VERSION 5.7 ;
BUSBITCHARS "[]" ;
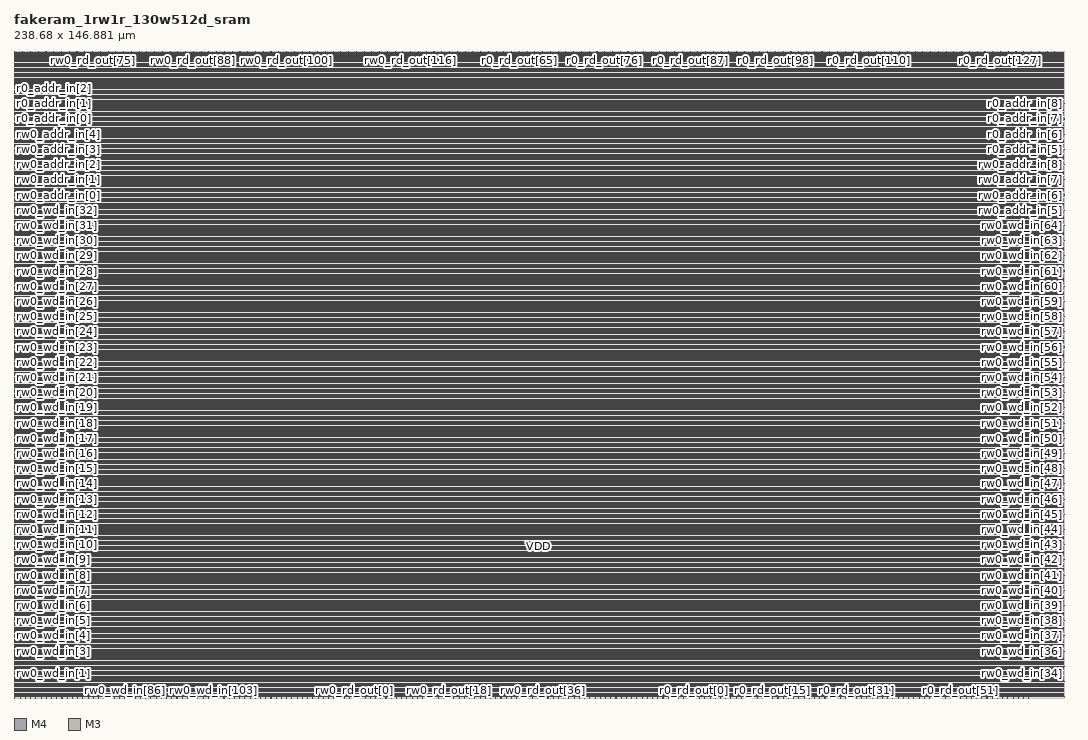
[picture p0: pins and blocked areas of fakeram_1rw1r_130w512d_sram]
MACRO fakeram_1rw1r_130w512d_sram
  FOREIGN fakeram_1rw1r_130w512d_sram 0 0 ;
  SYMMETRY X Y R90 ;
  SIZE 238.680 BY 146.881 ;
  CLASS BLOCK ;
  PIN rw0_wd_in[0]
    DIRECTION INPUT ;
    USE SIGNAL ;
    SHAPE ABUTMENT ;
    PORT
      LAYER M4 ;
      RECT 0.000 0.276 0.072 0.300 ;
    END
  END rw0_wd_in[0]
  PIN rw0_wd_in[1]
    DIRECTION INPUT ;
    USE SIGNAL ;
    SHAPE ABUTMENT ;
    PORT
      LAYER M4 ;
      RECT 0.000 3.732 0.072 3.756 ;
    END
  END rw0_wd_in[1]
  PIN rw0_wd_in[2]
    DIRECTION INPUT ;
    USE SIGNAL ;
    SHAPE ABUTMENT ;
    PORT
      LAYER M4 ;
      RECT 0.000 7.188 0.072 7.212 ;
    END
  END rw0_wd_in[2]
  PIN rw0_wd_in[3]
    DIRECTION INPUT ;
    USE SIGNAL ;
    SHAPE ABUTMENT ;
    PORT
      LAYER M4 ;
      RECT 0.000 10.644 0.072 10.668 ;
    END
  END rw0_wd_in[3]
  PIN rw0_wd_in[4]
    DIRECTION INPUT ;
    USE SIGNAL ;
    SHAPE ABUTMENT ;
    PORT
      LAYER M4 ;
      RECT 0.000 14.100 0.072 14.124 ;
    END
  END rw0_wd_in[4]
  PIN rw0_wd_in[5]
    DIRECTION INPUT ;
    USE SIGNAL ;
    SHAPE ABUTMENT ;
    PORT
      LAYER M4 ;
      RECT 0.000 17.556 0.072 17.580 ;
    END
  END rw0_wd_in[5]
  PIN rw0_wd_in[6]
    DIRECTION INPUT ;
    USE SIGNAL ;
    SHAPE ABUTMENT ;
    PORT
      LAYER M4 ;
      RECT 0.000 21.012 0.072 21.036 ;
    END
  END rw0_wd_in[6]
  PIN rw0_wd_in[7]
    DIRECTION INPUT ;
    USE SIGNAL ;
    SHAPE ABUTMENT ;
    PORT
      LAYER M4 ;
      RECT 0.000 24.468 0.072 24.492 ;
    END
  END rw0_wd_in[7]
  PIN rw0_wd_in[8]
    DIRECTION INPUT ;
    USE SIGNAL ;
    SHAPE ABUTMENT ;
    PORT
      LAYER M4 ;
      RECT 0.000 27.924 0.072 27.948 ;
    END
  END rw0_wd_in[8]
  PIN rw0_wd_in[9]
    DIRECTION INPUT ;
    USE SIGNAL ;
    SHAPE ABUTMENT ;
    PORT
      LAYER M4 ;
      RECT 0.000 31.380 0.072 31.404 ;
    END
  END rw0_wd_in[9]
  PIN rw0_wd_in[10]
    DIRECTION INPUT ;
    USE SIGNAL ;
    SHAPE ABUTMENT ;
    PORT
      LAYER M4 ;
      RECT 0.000 34.836 0.072 34.860 ;
    END
  END rw0_wd_in[10]
  PIN rw0_wd_in[11]
    DIRECTION INPUT ;
    USE SIGNAL ;
    SHAPE ABUTMENT ;
    PORT
      LAYER M4 ;
      RECT 0.000 38.292 0.072 38.316 ;
    END
  END rw0_wd_in[11]
  PIN rw0_wd_in[12]
    DIRECTION INPUT ;
    USE SIGNAL ;
    SHAPE ABUTMENT ;
    PORT
      LAYER M4 ;
      RECT 0.000 41.748 0.072 41.772 ;
    END
  END rw0_wd_in[12]
  PIN rw0_wd_in[13]
    DIRECTION INPUT ;
    USE SIGNAL ;
    SHAPE ABUTMENT ;
    PORT
      LAYER M4 ;
      RECT 0.000 45.204 0.072 45.228 ;
    END
  END rw0_wd_in[13]
  PIN rw0_wd_in[14]
    DIRECTION INPUT ;
    USE SIGNAL ;
    SHAPE ABUTMENT ;
    PORT
      LAYER M4 ;
      RECT 0.000 48.660 0.072 48.684 ;
    END
  END rw0_wd_in[14]
  PIN rw0_wd_in[15]
    DIRECTION INPUT ;
    USE SIGNAL ;
    SHAPE ABUTMENT ;
    PORT
      LAYER M4 ;
      RECT 0.000 52.116 0.072 52.140 ;
    END
  END rw0_wd_in[15]
  PIN rw0_wd_in[16]
    DIRECTION INPUT ;
    USE SIGNAL ;
    SHAPE ABUTMENT ;
    PORT
      LAYER M4 ;
      RECT 0.000 55.572 0.072 55.596 ;
    END
  END rw0_wd_in[16]
  PIN rw0_wd_in[17]
    DIRECTION INPUT ;
    USE SIGNAL ;
    SHAPE ABUTMENT ;
    PORT
      LAYER M4 ;
      RECT 0.000 59.028 0.072 59.052 ;
    END
  END rw0_wd_in[17]
  PIN rw0_wd_in[18]
    DIRECTION INPUT ;
    USE SIGNAL ;
    SHAPE ABUTMENT ;
    PORT
      LAYER M4 ;
      RECT 0.000 62.484 0.072 62.508 ;
    END
  END rw0_wd_in[18]
  PIN rw0_wd_in[19]
    DIRECTION INPUT ;
    USE SIGNAL ;
    SHAPE ABUTMENT ;
    PORT
      LAYER M4 ;
      RECT 0.000 65.940 0.072 65.964 ;
    END
  END rw0_wd_in[19]
  PIN rw0_wd_in[20]
    DIRECTION INPUT ;
    USE SIGNAL ;
    SHAPE ABUTMENT ;
    PORT
      LAYER M4 ;
      RECT 0.000 69.396 0.072 69.420 ;
    END
  END rw0_wd_in[20]
  PIN rw0_wd_in[21]
    DIRECTION INPUT ;
    USE SIGNAL ;
    SHAPE ABUTMENT ;
    PORT
      LAYER M4 ;
      RECT 0.000 72.852 0.072 72.876 ;
    END
  END rw0_wd_in[21]
  PIN rw0_wd_in[22]
    DIRECTION INPUT ;
    USE SIGNAL ;
    SHAPE ABUTMENT ;
    PORT
      LAYER M4 ;
      RECT 0.000 76.308 0.072 76.332 ;
    END
  END rw0_wd_in[22]
  PIN rw0_wd_in[23]
    DIRECTION INPUT ;
    USE SIGNAL ;
    SHAPE ABUTMENT ;
    PORT
      LAYER M4 ;
      RECT 0.000 79.764 0.072 79.788 ;
    END
  END rw0_wd_in[23]
  PIN rw0_wd_in[24]
    DIRECTION INPUT ;
    USE SIGNAL ;
    SHAPE ABUTMENT ;
    PORT
      LAYER M4 ;
      RECT 0.000 83.220 0.072 83.244 ;
    END
  END rw0_wd_in[24]
  PIN rw0_wd_in[25]
    DIRECTION INPUT ;
    USE SIGNAL ;
    SHAPE ABUTMENT ;
    PORT
      LAYER M4 ;
      RECT 0.000 86.676 0.072 86.700 ;
    END
  END rw0_wd_in[25]
  PIN rw0_wd_in[26]
    DIRECTION INPUT ;
    USE SIGNAL ;
    SHAPE ABUTMENT ;
    PORT
      LAYER M4 ;
      RECT 0.000 90.132 0.072 90.156 ;
    END
  END rw0_wd_in[26]
  PIN rw0_wd_in[27]
    DIRECTION INPUT ;
    USE SIGNAL ;
    SHAPE ABUTMENT ;
    PORT
      LAYER M4 ;
      RECT 0.000 93.588 0.072 93.612 ;
    END
  END rw0_wd_in[27]
  PIN rw0_wd_in[28]
    DIRECTION INPUT ;
    USE SIGNAL ;
    SHAPE ABUTMENT ;
    PORT
      LAYER M4 ;
      RECT 0.000 97.044 0.072 97.068 ;
    END
  END rw0_wd_in[28]
  PIN rw0_wd_in[29]
    DIRECTION INPUT ;
    USE SIGNAL ;
    SHAPE ABUTMENT ;
    PORT
      LAYER M4 ;
      RECT 0.000 100.500 0.072 100.524 ;
    END
  END rw0_wd_in[29]
  PIN rw0_wd_in[30]
    DIRECTION INPUT ;
    USE SIGNAL ;
    SHAPE ABUTMENT ;
    PORT
      LAYER M4 ;
      RECT 0.000 103.956 0.072 103.980 ;
    END
  END rw0_wd_in[30]
  PIN rw0_wd_in[31]
    DIRECTION INPUT ;
    USE SIGNAL ;
    SHAPE ABUTMENT ;
    PORT
      LAYER M4 ;
      RECT 0.000 107.412 0.072 107.436 ;
    END
  END rw0_wd_in[31]
  PIN rw0_wd_in[32]
    DIRECTION INPUT ;
    USE SIGNAL ;
    SHAPE ABUTMENT ;
    PORT
      LAYER M4 ;
      RECT 0.000 110.868 0.072 110.892 ;
    END
  END rw0_wd_in[32]
  PIN rw0_wd_in[33]
    DIRECTION INPUT ;
    USE SIGNAL ;
    SHAPE ABUTMENT ;
    PORT
      LAYER M4 ;
      RECT 238.608 0.276 238.680 0.300 ;
    END
  END rw0_wd_in[33]
  PIN rw0_wd_in[34]
    DIRECTION INPUT ;
    USE SIGNAL ;
    SHAPE ABUTMENT ;
    PORT
      LAYER M4 ;
      RECT 238.608 3.732 238.680 3.756 ;
    END
  END rw0_wd_in[34]
  PIN rw0_wd_in[35]
    DIRECTION INPUT ;
    USE SIGNAL ;
    SHAPE ABUTMENT ;
    PORT
      LAYER M4 ;
      RECT 238.608 7.188 238.680 7.212 ;
    END
  END rw0_wd_in[35]
  PIN rw0_wd_in[36]
    DIRECTION INPUT ;
    USE SIGNAL ;
    SHAPE ABUTMENT ;
    PORT
      LAYER M4 ;
      RECT 238.608 10.644 238.680 10.668 ;
    END
  END rw0_wd_in[36]
  PIN rw0_wd_in[37]
    DIRECTION INPUT ;
    USE SIGNAL ;
    SHAPE ABUTMENT ;
    PORT
      LAYER M4 ;
      RECT 238.608 14.100 238.680 14.124 ;
    END
  END rw0_wd_in[37]
  PIN rw0_wd_in[38]
    DIRECTION INPUT ;
    USE SIGNAL ;
    SHAPE ABUTMENT ;
    PORT
      LAYER M4 ;
      RECT 238.608 17.556 238.680 17.580 ;
    END
  END rw0_wd_in[38]
  PIN rw0_wd_in[39]
    DIRECTION INPUT ;
    USE SIGNAL ;
    SHAPE ABUTMENT ;
    PORT
      LAYER M4 ;
      RECT 238.608 21.012 238.680 21.036 ;
    END
  END rw0_wd_in[39]
  PIN rw0_wd_in[40]
    DIRECTION INPUT ;
    USE SIGNAL ;
    SHAPE ABUTMENT ;
    PORT
      LAYER M4 ;
      RECT 238.608 24.468 238.680 24.492 ;
    END
  END rw0_wd_in[40]
  PIN rw0_wd_in[41]
    DIRECTION INPUT ;
    USE SIGNAL ;
    SHAPE ABUTMENT ;
    PORT
      LAYER M4 ;
      RECT 238.608 27.924 238.680 27.948 ;
    END
  END rw0_wd_in[41]
  PIN rw0_wd_in[42]
    DIRECTION INPUT ;
    USE SIGNAL ;
    SHAPE ABUTMENT ;
    PORT
      LAYER M4 ;
      RECT 238.608 31.380 238.680 31.404 ;
    END
  END rw0_wd_in[42]
  PIN rw0_wd_in[43]
    DIRECTION INPUT ;
    USE SIGNAL ;
    SHAPE ABUTMENT ;
    PORT
      LAYER M4 ;
      RECT 238.608 34.836 238.680 34.860 ;
    END
  END rw0_wd_in[43]
  PIN rw0_wd_in[44]
    DIRECTION INPUT ;
    USE SIGNAL ;
    SHAPE ABUTMENT ;
    PORT
      LAYER M4 ;
      RECT 238.608 38.292 238.680 38.316 ;
    END
  END rw0_wd_in[44]
  PIN rw0_wd_in[45]
    DIRECTION INPUT ;
    USE SIGNAL ;
    SHAPE ABUTMENT ;
    PORT
      LAYER M4 ;
      RECT 238.608 41.748 238.680 41.772 ;
    END
  END rw0_wd_in[45]
  PIN rw0_wd_in[46]
    DIRECTION INPUT ;
    USE SIGNAL ;
    SHAPE ABUTMENT ;
    PORT
      LAYER M4 ;
      RECT 238.608 45.204 238.680 45.228 ;
    END
  END rw0_wd_in[46]
  PIN rw0_wd_in[47]
    DIRECTION INPUT ;
    USE SIGNAL ;
    SHAPE ABUTMENT ;
    PORT
      LAYER M4 ;
      RECT 238.608 48.660 238.680 48.684 ;
    END
  END rw0_wd_in[47]
  PIN rw0_wd_in[48]
    DIRECTION INPUT ;
    USE SIGNAL ;
    SHAPE ABUTMENT ;
    PORT
      LAYER M4 ;
      RECT 238.608 52.116 238.680 52.140 ;
    END
  END rw0_wd_in[48]
  PIN rw0_wd_in[49]
    DIRECTION INPUT ;
    USE SIGNAL ;
    SHAPE ABUTMENT ;
    PORT
      LAYER M4 ;
      RECT 238.608 55.572 238.680 55.596 ;
    END
  END rw0_wd_in[49]
  PIN rw0_wd_in[50]
    DIRECTION INPUT ;
    USE SIGNAL ;
    SHAPE ABUTMENT ;
    PORT
      LAYER M4 ;
      RECT 238.608 59.028 238.680 59.052 ;
    END
  END rw0_wd_in[50]
  PIN rw0_wd_in[51]
    DIRECTION INPUT ;
    USE SIGNAL ;
    SHAPE ABUTMENT ;
    PORT
      LAYER M4 ;
      RECT 238.608 62.484 238.680 62.508 ;
    END
  END rw0_wd_in[51]
  PIN rw0_wd_in[52]
    DIRECTION INPUT ;
    USE SIGNAL ;
    SHAPE ABUTMENT ;
    PORT
      LAYER M4 ;
      RECT 238.608 65.940 238.680 65.964 ;
    END
  END rw0_wd_in[52]
  PIN rw0_wd_in[53]
    DIRECTION INPUT ;
    USE SIGNAL ;
    SHAPE ABUTMENT ;
    PORT
      LAYER M4 ;
      RECT 238.608 69.396 238.680 69.420 ;
    END
  END rw0_wd_in[53]
  PIN rw0_wd_in[54]
    DIRECTION INPUT ;
    USE SIGNAL ;
    SHAPE ABUTMENT ;
    PORT
      LAYER M4 ;
      RECT 238.608 72.852 238.680 72.876 ;
    END
  END rw0_wd_in[54]
  PIN rw0_wd_in[55]
    DIRECTION INPUT ;
    USE SIGNAL ;
    SHAPE ABUTMENT ;
    PORT
      LAYER M4 ;
      RECT 238.608 76.308 238.680 76.332 ;
    END
  END rw0_wd_in[55]
  PIN rw0_wd_in[56]
    DIRECTION INPUT ;
    USE SIGNAL ;
    SHAPE ABUTMENT ;
    PORT
      LAYER M4 ;
      RECT 238.608 79.764 238.680 79.788 ;
    END
  END rw0_wd_in[56]
  PIN rw0_wd_in[57]
    DIRECTION INPUT ;
    USE SIGNAL ;
    SHAPE ABUTMENT ;
    PORT
      LAYER M4 ;
      RECT 238.608 83.220 238.680 83.244 ;
    END
  END rw0_wd_in[57]
  PIN rw0_wd_in[58]
    DIRECTION INPUT ;
    USE SIGNAL ;
    SHAPE ABUTMENT ;
    PORT
      LAYER M4 ;
      RECT 238.608 86.676 238.680 86.700 ;
    END
  END rw0_wd_in[58]
  PIN rw0_wd_in[59]
    DIRECTION INPUT ;
    USE SIGNAL ;
    SHAPE ABUTMENT ;
    PORT
      LAYER M4 ;
      RECT 238.608 90.132 238.680 90.156 ;
    END
  END rw0_wd_in[59]
  PIN rw0_wd_in[60]
    DIRECTION INPUT ;
    USE SIGNAL ;
    SHAPE ABUTMENT ;
    PORT
      LAYER M4 ;
      RECT 238.608 93.588 238.680 93.612 ;
    END
  END rw0_wd_in[60]
  PIN rw0_wd_in[61]
    DIRECTION INPUT ;
    USE SIGNAL ;
    SHAPE ABUTMENT ;
    PORT
      LAYER M4 ;
      RECT 238.608 97.044 238.680 97.068 ;
    END
  END rw0_wd_in[61]
  PIN rw0_wd_in[62]
    DIRECTION INPUT ;
    USE SIGNAL ;
    SHAPE ABUTMENT ;
    PORT
      LAYER M4 ;
      RECT 238.608 100.500 238.680 100.524 ;
    END
  END rw0_wd_in[62]
  PIN rw0_wd_in[63]
    DIRECTION INPUT ;
    USE SIGNAL ;
    SHAPE ABUTMENT ;
    PORT
      LAYER M4 ;
      RECT 238.608 103.956 238.680 103.980 ;
    END
  END rw0_wd_in[63]
  PIN rw0_wd_in[64]
    DIRECTION INPUT ;
    USE SIGNAL ;
    SHAPE ABUTMENT ;
    PORT
      LAYER M4 ;
      RECT 238.608 107.412 238.680 107.436 ;
    END
  END rw0_wd_in[64]
  PIN rw0_wd_in[65]
    DIRECTION INPUT ;
    USE SIGNAL ;
    SHAPE ABUTMENT ;
    PORT
      LAYER M3 ;
      RECT 0.207 0.000 0.225 0.054 ;
    END
  END rw0_wd_in[65]
  PIN rw0_wd_in[66]
    DIRECTION INPUT ;
    USE SIGNAL ;
    SHAPE ABUTMENT ;
    PORT
      LAYER M3 ;
      RECT 1.395 0.000 1.413 0.054 ;
    END
  END rw0_wd_in[66]
  PIN rw0_wd_in[67]
    DIRECTION INPUT ;
    USE SIGNAL ;
    SHAPE ABUTMENT ;
    PORT
      LAYER M3 ;
      RECT 2.583 0.000 2.601 0.054 ;
    END
  END rw0_wd_in[67]
  PIN rw0_wd_in[68]
    DIRECTION INPUT ;
    USE SIGNAL ;
    SHAPE ABUTMENT ;
    PORT
      LAYER M3 ;
      RECT 3.771 0.000 3.789 0.054 ;
    END
  END rw0_wd_in[68]
  PIN rw0_wd_in[69]
    DIRECTION INPUT ;
    USE SIGNAL ;
    SHAPE ABUTMENT ;
    PORT
      LAYER M3 ;
      RECT 4.959 0.000 4.977 0.054 ;
    END
  END rw0_wd_in[69]
  PIN rw0_wd_in[70]
    DIRECTION INPUT ;
    USE SIGNAL ;
    SHAPE ABUTMENT ;
    PORT
      LAYER M3 ;
      RECT 6.147 0.000 6.165 0.054 ;
    END
  END rw0_wd_in[70]
  PIN rw0_wd_in[71]
    DIRECTION INPUT ;
    USE SIGNAL ;
    SHAPE ABUTMENT ;
    PORT
      LAYER M3 ;
      RECT 7.335 0.000 7.353 0.054 ;
    END
  END rw0_wd_in[71]
  PIN rw0_wd_in[72]
    DIRECTION INPUT ;
    USE SIGNAL ;
    SHAPE ABUTMENT ;
    PORT
      LAYER M3 ;
      RECT 8.523 0.000 8.541 0.054 ;
    END
  END rw0_wd_in[72]
  PIN rw0_wd_in[73]
    DIRECTION INPUT ;
    USE SIGNAL ;
    SHAPE ABUTMENT ;
    PORT
      LAYER M3 ;
      RECT 9.711 0.000 9.729 0.054 ;
    END
  END rw0_wd_in[73]
  PIN rw0_wd_in[74]
    DIRECTION INPUT ;
    USE SIGNAL ;
    SHAPE ABUTMENT ;
    PORT
      LAYER M3 ;
      RECT 10.899 0.000 10.917 0.054 ;
    END
  END rw0_wd_in[74]
  PIN rw0_wd_in[75]
    DIRECTION INPUT ;
    USE SIGNAL ;
    SHAPE ABUTMENT ;
    PORT
      LAYER M3 ;
      RECT 12.087 0.000 12.105 0.054 ;
    END
  END rw0_wd_in[75]
  PIN rw0_wd_in[76]
    DIRECTION INPUT ;
    USE SIGNAL ;
    SHAPE ABUTMENT ;
    PORT
      LAYER M3 ;
      RECT 13.275 0.000 13.293 0.054 ;
    END
  END rw0_wd_in[76]
  PIN rw0_wd_in[77]
    DIRECTION INPUT ;
    USE SIGNAL ;
    SHAPE ABUTMENT ;
    PORT
      LAYER M3 ;
      RECT 14.463 0.000 14.481 0.054 ;
    END
  END rw0_wd_in[77]
  PIN rw0_wd_in[78]
    DIRECTION INPUT ;
    USE SIGNAL ;
    SHAPE ABUTMENT ;
    PORT
      LAYER M3 ;
      RECT 15.651 0.000 15.669 0.054 ;
    END
  END rw0_wd_in[78]
  PIN rw0_wd_in[79]
    DIRECTION INPUT ;
    USE SIGNAL ;
    SHAPE ABUTMENT ;
    PORT
      LAYER M3 ;
      RECT 16.839 0.000 16.857 0.054 ;
    END
  END rw0_wd_in[79]
  PIN rw0_wd_in[80]
    DIRECTION INPUT ;
    USE SIGNAL ;
    SHAPE ABUTMENT ;
    PORT
      LAYER M3 ;
      RECT 18.027 0.000 18.045 0.054 ;
    END
  END rw0_wd_in[80]
  PIN rw0_wd_in[81]
    DIRECTION INPUT ;
    USE SIGNAL ;
    SHAPE ABUTMENT ;
    PORT
      LAYER M3 ;
      RECT 19.215 0.000 19.233 0.054 ;
    END
  END rw0_wd_in[81]
  PIN rw0_wd_in[82]
    DIRECTION INPUT ;
    USE SIGNAL ;
    SHAPE ABUTMENT ;
    PORT
      LAYER M3 ;
      RECT 20.403 0.000 20.421 0.054 ;
    END
  END rw0_wd_in[82]
  PIN rw0_wd_in[83]
    DIRECTION INPUT ;
    USE SIGNAL ;
    SHAPE ABUTMENT ;
    PORT
      LAYER M3 ;
      RECT 21.591 0.000 21.609 0.054 ;
    END
  END rw0_wd_in[83]
  PIN rw0_wd_in[84]
    DIRECTION INPUT ;
    USE SIGNAL ;
    SHAPE ABUTMENT ;
    PORT
      LAYER M3 ;
      RECT 22.779 0.000 22.797 0.054 ;
    END
  END rw0_wd_in[84]
  PIN rw0_wd_in[85]
    DIRECTION INPUT ;
    USE SIGNAL ;
    SHAPE ABUTMENT ;
    PORT
      LAYER M3 ;
      RECT 23.967 0.000 23.985 0.054 ;
    END
  END rw0_wd_in[85]
  PIN rw0_wd_in[86]
    DIRECTION INPUT ;
    USE SIGNAL ;
    SHAPE ABUTMENT ;
    PORT
      LAYER M3 ;
      RECT 25.155 0.000 25.173 0.054 ;
    END
  END rw0_wd_in[86]
  PIN rw0_wd_in[87]
    DIRECTION INPUT ;
    USE SIGNAL ;
    SHAPE ABUTMENT ;
    PORT
      LAYER M3 ;
      RECT 26.343 0.000 26.361 0.054 ;
    END
  END rw0_wd_in[87]
  PIN rw0_wd_in[88]
    DIRECTION INPUT ;
    USE SIGNAL ;
    SHAPE ABUTMENT ;
    PORT
      LAYER M3 ;
      RECT 27.531 0.000 27.549 0.054 ;
    END
  END rw0_wd_in[88]
  PIN rw0_wd_in[89]
    DIRECTION INPUT ;
    USE SIGNAL ;
    SHAPE ABUTMENT ;
    PORT
      LAYER M3 ;
      RECT 28.719 0.000 28.737 0.054 ;
    END
  END rw0_wd_in[89]
  PIN rw0_wd_in[90]
    DIRECTION INPUT ;
    USE SIGNAL ;
    SHAPE ABUTMENT ;
    PORT
      LAYER M3 ;
      RECT 29.907 0.000 29.925 0.054 ;
    END
  END rw0_wd_in[90]
  PIN rw0_wd_in[91]
    DIRECTION INPUT ;
    USE SIGNAL ;
    SHAPE ABUTMENT ;
    PORT
      LAYER M3 ;
      RECT 31.095 0.000 31.113 0.054 ;
    END
  END rw0_wd_in[91]
  PIN rw0_wd_in[92]
    DIRECTION INPUT ;
    USE SIGNAL ;
    SHAPE ABUTMENT ;
    PORT
      LAYER M3 ;
      RECT 32.283 0.000 32.301 0.054 ;
    END
  END rw0_wd_in[92]
  PIN rw0_wd_in[93]
    DIRECTION INPUT ;
    USE SIGNAL ;
    SHAPE ABUTMENT ;
    PORT
      LAYER M3 ;
      RECT 33.471 0.000 33.489 0.054 ;
    END
  END rw0_wd_in[93]
  PIN rw0_wd_in[94]
    DIRECTION INPUT ;
    USE SIGNAL ;
    SHAPE ABUTMENT ;
    PORT
      LAYER M3 ;
      RECT 34.659 0.000 34.677 0.054 ;
    END
  END rw0_wd_in[94]
  PIN rw0_wd_in[95]
    DIRECTION INPUT ;
    USE SIGNAL ;
    SHAPE ABUTMENT ;
    PORT
      LAYER M3 ;
      RECT 35.847 0.000 35.865 0.054 ;
    END
  END rw0_wd_in[95]
  PIN rw0_wd_in[96]
    DIRECTION INPUT ;
    USE SIGNAL ;
    SHAPE ABUTMENT ;
    PORT
      LAYER M3 ;
      RECT 37.035 0.000 37.053 0.054 ;
    END
  END rw0_wd_in[96]
  PIN rw0_wd_in[97]
    DIRECTION INPUT ;
    USE SIGNAL ;
    SHAPE ABUTMENT ;
    PORT
      LAYER M3 ;
      RECT 38.223 0.000 38.241 0.054 ;
    END
  END rw0_wd_in[97]
  PIN rw0_wd_in[98]
    DIRECTION INPUT ;
    USE SIGNAL ;
    SHAPE ABUTMENT ;
    PORT
      LAYER M3 ;
      RECT 39.411 0.000 39.429 0.054 ;
    END
  END rw0_wd_in[98]
  PIN rw0_wd_in[99]
    DIRECTION INPUT ;
    USE SIGNAL ;
    SHAPE ABUTMENT ;
    PORT
      LAYER M3 ;
      RECT 40.599 0.000 40.617 0.054 ;
    END
  END rw0_wd_in[99]
  PIN rw0_wd_in[100]
    DIRECTION INPUT ;
    USE SIGNAL ;
    SHAPE ABUTMENT ;
    PORT
      LAYER M3 ;
      RECT 41.787 0.000 41.805 0.054 ;
    END
  END rw0_wd_in[100]
  PIN rw0_wd_in[101]
    DIRECTION INPUT ;
    USE SIGNAL ;
    SHAPE ABUTMENT ;
    PORT
      LAYER M3 ;
      RECT 42.975 0.000 42.993 0.054 ;
    END
  END rw0_wd_in[101]
  PIN rw0_wd_in[102]
    DIRECTION INPUT ;
    USE SIGNAL ;
    SHAPE ABUTMENT ;
    PORT
      LAYER M3 ;
      RECT 44.163 0.000 44.181 0.054 ;
    END
  END rw0_wd_in[102]
  PIN rw0_wd_in[103]
    DIRECTION INPUT ;
    USE SIGNAL ;
    SHAPE ABUTMENT ;
    PORT
      LAYER M3 ;
      RECT 45.351 0.000 45.369 0.054 ;
    END
  END rw0_wd_in[103]
  PIN rw0_wd_in[104]
    DIRECTION INPUT ;
    USE SIGNAL ;
    SHAPE ABUTMENT ;
    PORT
      LAYER M3 ;
      RECT 46.539 0.000 46.557 0.054 ;
    END
  END rw0_wd_in[104]
  PIN rw0_wd_in[105]
    DIRECTION INPUT ;
    USE SIGNAL ;
    SHAPE ABUTMENT ;
    PORT
      LAYER M3 ;
      RECT 47.727 0.000 47.745 0.054 ;
    END
  END rw0_wd_in[105]
  PIN rw0_wd_in[106]
    DIRECTION INPUT ;
    USE SIGNAL ;
    SHAPE ABUTMENT ;
    PORT
      LAYER M3 ;
      RECT 48.915 0.000 48.933 0.054 ;
    END
  END rw0_wd_in[106]
  PIN rw0_wd_in[107]
    DIRECTION INPUT ;
    USE SIGNAL ;
    SHAPE ABUTMENT ;
    PORT
      LAYER M3 ;
      RECT 50.103 0.000 50.121 0.054 ;
    END
  END rw0_wd_in[107]
  PIN rw0_wd_in[108]
    DIRECTION INPUT ;
    USE SIGNAL ;
    SHAPE ABUTMENT ;
    PORT
      LAYER M3 ;
      RECT 51.291 0.000 51.309 0.054 ;
    END
  END rw0_wd_in[108]
  PIN rw0_wd_in[109]
    DIRECTION INPUT ;
    USE SIGNAL ;
    SHAPE ABUTMENT ;
    PORT
      LAYER M3 ;
      RECT 52.479 0.000 52.497 0.054 ;
    END
  END rw0_wd_in[109]
  PIN rw0_wd_in[110]
    DIRECTION INPUT ;
    USE SIGNAL ;
    SHAPE ABUTMENT ;
    PORT
      LAYER M3 ;
      RECT 53.667 0.000 53.685 0.054 ;
    END
  END rw0_wd_in[110]
  PIN rw0_wd_in[111]
    DIRECTION INPUT ;
    USE SIGNAL ;
    SHAPE ABUTMENT ;
    PORT
      LAYER M3 ;
      RECT 54.855 0.000 54.873 0.054 ;
    END
  END rw0_wd_in[111]
  PIN rw0_wd_in[112]
    DIRECTION INPUT ;
    USE SIGNAL ;
    SHAPE ABUTMENT ;
    PORT
      LAYER M3 ;
      RECT 56.043 0.000 56.061 0.054 ;
    END
  END rw0_wd_in[112]
  PIN rw0_wd_in[113]
    DIRECTION INPUT ;
    USE SIGNAL ;
    SHAPE ABUTMENT ;
    PORT
      LAYER M3 ;
      RECT 57.231 0.000 57.249 0.054 ;
    END
  END rw0_wd_in[113]
  PIN rw0_wd_in[114]
    DIRECTION INPUT ;
    USE SIGNAL ;
    SHAPE ABUTMENT ;
    PORT
      LAYER M3 ;
      RECT 58.419 0.000 58.437 0.054 ;
    END
  END rw0_wd_in[114]
  PIN rw0_wd_in[115]
    DIRECTION INPUT ;
    USE SIGNAL ;
    SHAPE ABUTMENT ;
    PORT
      LAYER M3 ;
      RECT 59.607 0.000 59.625 0.054 ;
    END
  END rw0_wd_in[115]
  PIN rw0_wd_in[116]
    DIRECTION INPUT ;
    USE SIGNAL ;
    SHAPE ABUTMENT ;
    PORT
      LAYER M3 ;
      RECT 60.795 0.000 60.813 0.054 ;
    END
  END rw0_wd_in[116]
  PIN rw0_wd_in[117]
    DIRECTION INPUT ;
    USE SIGNAL ;
    SHAPE ABUTMENT ;
    PORT
      LAYER M3 ;
      RECT 61.983 0.000 62.001 0.054 ;
    END
  END rw0_wd_in[117]
  PIN rw0_wd_in[118]
    DIRECTION INPUT ;
    USE SIGNAL ;
    SHAPE ABUTMENT ;
    PORT
      LAYER M3 ;
      RECT 63.171 0.000 63.189 0.054 ;
    END
  END rw0_wd_in[118]
  PIN rw0_wd_in[119]
    DIRECTION INPUT ;
    USE SIGNAL ;
    SHAPE ABUTMENT ;
    PORT
      LAYER M3 ;
      RECT 64.359 0.000 64.377 0.054 ;
    END
  END rw0_wd_in[119]
  PIN rw0_wd_in[120]
    DIRECTION INPUT ;
    USE SIGNAL ;
    SHAPE ABUTMENT ;
    PORT
      LAYER M3 ;
      RECT 65.547 0.000 65.565 0.054 ;
    END
  END rw0_wd_in[120]
  PIN rw0_wd_in[121]
    DIRECTION INPUT ;
    USE SIGNAL ;
    SHAPE ABUTMENT ;
    PORT
      LAYER M3 ;
      RECT 66.735 0.000 66.753 0.054 ;
    END
  END rw0_wd_in[121]
  PIN rw0_wd_in[122]
    DIRECTION INPUT ;
    USE SIGNAL ;
    SHAPE ABUTMENT ;
    PORT
      LAYER M3 ;
      RECT 67.923 0.000 67.941 0.054 ;
    END
  END rw0_wd_in[122]
  PIN rw0_wd_in[123]
    DIRECTION INPUT ;
    USE SIGNAL ;
    SHAPE ABUTMENT ;
    PORT
      LAYER M3 ;
      RECT 69.111 0.000 69.129 0.054 ;
    END
  END rw0_wd_in[123]
  PIN rw0_wd_in[124]
    DIRECTION INPUT ;
    USE SIGNAL ;
    SHAPE ABUTMENT ;
    PORT
      LAYER M3 ;
      RECT 70.299 0.000 70.317 0.054 ;
    END
  END rw0_wd_in[124]
  PIN rw0_wd_in[125]
    DIRECTION INPUT ;
    USE SIGNAL ;
    SHAPE ABUTMENT ;
    PORT
      LAYER M3 ;
      RECT 71.487 0.000 71.505 0.054 ;
    END
  END rw0_wd_in[125]
  PIN rw0_wd_in[126]
    DIRECTION INPUT ;
    USE SIGNAL ;
    SHAPE ABUTMENT ;
    PORT
      LAYER M3 ;
      RECT 72.675 0.000 72.693 0.054 ;
    END
  END rw0_wd_in[126]
  PIN rw0_wd_in[127]
    DIRECTION INPUT ;
    USE SIGNAL ;
    SHAPE ABUTMENT ;
    PORT
      LAYER M3 ;
      RECT 73.863 0.000 73.881 0.054 ;
    END
  END rw0_wd_in[127]
  PIN rw0_wd_in[128]
    DIRECTION INPUT ;
    USE SIGNAL ;
    SHAPE ABUTMENT ;
    PORT
      LAYER M3 ;
      RECT 75.051 0.000 75.069 0.054 ;
    END
  END rw0_wd_in[128]
  PIN rw0_wd_in[129]
    DIRECTION INPUT ;
    USE SIGNAL ;
    SHAPE ABUTMENT ;
    PORT
      LAYER M3 ;
      RECT 76.239 0.000 76.257 0.054 ;
    END
  END rw0_wd_in[129]
  PIN rw0_rd_out[0]
    DIRECTION OUTPUT ;
    USE SIGNAL ;
    SHAPE ABUTMENT ;
    PORT
      LAYER M3 ;
      RECT 77.427 0.000 77.445 0.054 ;
    END
  END rw0_rd_out[0]
  PIN rw0_rd_out[1]
    DIRECTION OUTPUT ;
    USE SIGNAL ;
    SHAPE ABUTMENT ;
    PORT
      LAYER M3 ;
      RECT 78.615 0.000 78.633 0.054 ;
    END
  END rw0_rd_out[1]
  PIN rw0_rd_out[2]
    DIRECTION OUTPUT ;
    USE SIGNAL ;
    SHAPE ABUTMENT ;
    PORT
      LAYER M3 ;
      RECT 79.803 0.000 79.821 0.054 ;
    END
  END rw0_rd_out[2]
  PIN rw0_rd_out[3]
    DIRECTION OUTPUT ;
    USE SIGNAL ;
    SHAPE ABUTMENT ;
    PORT
      LAYER M3 ;
      RECT 80.991 0.000 81.009 0.054 ;
    END
  END rw0_rd_out[3]
  PIN rw0_rd_out[4]
    DIRECTION OUTPUT ;
    USE SIGNAL ;
    SHAPE ABUTMENT ;
    PORT
      LAYER M3 ;
      RECT 82.179 0.000 82.197 0.054 ;
    END
  END rw0_rd_out[4]
  PIN rw0_rd_out[5]
    DIRECTION OUTPUT ;
    USE SIGNAL ;
    SHAPE ABUTMENT ;
    PORT
      LAYER M3 ;
      RECT 83.367 0.000 83.385 0.054 ;
    END
  END rw0_rd_out[5]
  PIN rw0_rd_out[6]
    DIRECTION OUTPUT ;
    USE SIGNAL ;
    SHAPE ABUTMENT ;
    PORT
      LAYER M3 ;
      RECT 84.555 0.000 84.573 0.054 ;
    END
  END rw0_rd_out[6]
  PIN rw0_rd_out[7]
    DIRECTION OUTPUT ;
    USE SIGNAL ;
    SHAPE ABUTMENT ;
    PORT
      LAYER M3 ;
      RECT 85.743 0.000 85.761 0.054 ;
    END
  END rw0_rd_out[7]
  PIN rw0_rd_out[8]
    DIRECTION OUTPUT ;
    USE SIGNAL ;
    SHAPE ABUTMENT ;
    PORT
      LAYER M3 ;
      RECT 86.931 0.000 86.949 0.054 ;
    END
  END rw0_rd_out[8]
  PIN rw0_rd_out[9]
    DIRECTION OUTPUT ;
    USE SIGNAL ;
    SHAPE ABUTMENT ;
    PORT
      LAYER M3 ;
      RECT 88.119 0.000 88.137 0.054 ;
    END
  END rw0_rd_out[9]
  PIN rw0_rd_out[10]
    DIRECTION OUTPUT ;
    USE SIGNAL ;
    SHAPE ABUTMENT ;
    PORT
      LAYER M3 ;
      RECT 89.307 0.000 89.325 0.054 ;
    END
  END rw0_rd_out[10]
  PIN rw0_rd_out[11]
    DIRECTION OUTPUT ;
    USE SIGNAL ;
    SHAPE ABUTMENT ;
    PORT
      LAYER M3 ;
      RECT 90.495 0.000 90.513 0.054 ;
    END
  END rw0_rd_out[11]
  PIN rw0_rd_out[12]
    DIRECTION OUTPUT ;
    USE SIGNAL ;
    SHAPE ABUTMENT ;
    PORT
      LAYER M3 ;
      RECT 91.683 0.000 91.701 0.054 ;
    END
  END rw0_rd_out[12]
  PIN rw0_rd_out[13]
    DIRECTION OUTPUT ;
    USE SIGNAL ;
    SHAPE ABUTMENT ;
    PORT
      LAYER M3 ;
      RECT 92.871 0.000 92.889 0.054 ;
    END
  END rw0_rd_out[13]
  PIN rw0_rd_out[14]
    DIRECTION OUTPUT ;
    USE SIGNAL ;
    SHAPE ABUTMENT ;
    PORT
      LAYER M3 ;
      RECT 94.059 0.000 94.077 0.054 ;
    END
  END rw0_rd_out[14]
  PIN rw0_rd_out[15]
    DIRECTION OUTPUT ;
    USE SIGNAL ;
    SHAPE ABUTMENT ;
    PORT
      LAYER M3 ;
      RECT 95.247 0.000 95.265 0.054 ;
    END
  END rw0_rd_out[15]
  PIN rw0_rd_out[16]
    DIRECTION OUTPUT ;
    USE SIGNAL ;
    SHAPE ABUTMENT ;
    PORT
      LAYER M3 ;
      RECT 96.435 0.000 96.453 0.054 ;
    END
  END rw0_rd_out[16]
  PIN rw0_rd_out[17]
    DIRECTION OUTPUT ;
    USE SIGNAL ;
    SHAPE ABUTMENT ;
    PORT
      LAYER M3 ;
      RECT 97.623 0.000 97.641 0.054 ;
    END
  END rw0_rd_out[17]
  PIN rw0_rd_out[18]
    DIRECTION OUTPUT ;
    USE SIGNAL ;
    SHAPE ABUTMENT ;
    PORT
      LAYER M3 ;
      RECT 98.811 0.000 98.829 0.054 ;
    END
  END rw0_rd_out[18]
  PIN rw0_rd_out[19]
    DIRECTION OUTPUT ;
    USE SIGNAL ;
    SHAPE ABUTMENT ;
    PORT
      LAYER M3 ;
      RECT 99.999 0.000 100.017 0.054 ;
    END
  END rw0_rd_out[19]
  PIN rw0_rd_out[20]
    DIRECTION OUTPUT ;
    USE SIGNAL ;
    SHAPE ABUTMENT ;
    PORT
      LAYER M3 ;
      RECT 101.187 0.000 101.205 0.054 ;
    END
  END rw0_rd_out[20]
  PIN rw0_rd_out[21]
    DIRECTION OUTPUT ;
    USE SIGNAL ;
    SHAPE ABUTMENT ;
    PORT
      LAYER M3 ;
      RECT 102.375 0.000 102.393 0.054 ;
    END
  END rw0_rd_out[21]
  PIN rw0_rd_out[22]
    DIRECTION OUTPUT ;
    USE SIGNAL ;
    SHAPE ABUTMENT ;
    PORT
      LAYER M3 ;
      RECT 103.563 0.000 103.581 0.054 ;
    END
  END rw0_rd_out[22]
  PIN rw0_rd_out[23]
    DIRECTION OUTPUT ;
    USE SIGNAL ;
    SHAPE ABUTMENT ;
    PORT
      LAYER M3 ;
      RECT 104.751 0.000 104.769 0.054 ;
    END
  END rw0_rd_out[23]
  PIN rw0_rd_out[24]
    DIRECTION OUTPUT ;
    USE SIGNAL ;
    SHAPE ABUTMENT ;
    PORT
      LAYER M3 ;
      RECT 105.939 0.000 105.957 0.054 ;
    END
  END rw0_rd_out[24]
  PIN rw0_rd_out[25]
    DIRECTION OUTPUT ;
    USE SIGNAL ;
    SHAPE ABUTMENT ;
    PORT
      LAYER M3 ;
      RECT 107.127 0.000 107.145 0.054 ;
    END
  END rw0_rd_out[25]
  PIN rw0_rd_out[26]
    DIRECTION OUTPUT ;
    USE SIGNAL ;
    SHAPE ABUTMENT ;
    PORT
      LAYER M3 ;
      RECT 108.315 0.000 108.333 0.054 ;
    END
  END rw0_rd_out[26]
  PIN rw0_rd_out[27]
    DIRECTION OUTPUT ;
    USE SIGNAL ;
    SHAPE ABUTMENT ;
    PORT
      LAYER M3 ;
      RECT 109.503 0.000 109.521 0.054 ;
    END
  END rw0_rd_out[27]
  PIN rw0_rd_out[28]
    DIRECTION OUTPUT ;
    USE SIGNAL ;
    SHAPE ABUTMENT ;
    PORT
      LAYER M3 ;
      RECT 110.691 0.000 110.709 0.054 ;
    END
  END rw0_rd_out[28]
  PIN rw0_rd_out[29]
    DIRECTION OUTPUT ;
    USE SIGNAL ;
    SHAPE ABUTMENT ;
    PORT
      LAYER M3 ;
      RECT 111.879 0.000 111.897 0.054 ;
    END
  END rw0_rd_out[29]
  PIN rw0_rd_out[30]
    DIRECTION OUTPUT ;
    USE SIGNAL ;
    SHAPE ABUTMENT ;
    PORT
      LAYER M3 ;
      RECT 113.067 0.000 113.085 0.054 ;
    END
  END rw0_rd_out[30]
  PIN rw0_rd_out[31]
    DIRECTION OUTPUT ;
    USE SIGNAL ;
    SHAPE ABUTMENT ;
    PORT
      LAYER M3 ;
      RECT 114.255 0.000 114.273 0.054 ;
    END
  END rw0_rd_out[31]
  PIN rw0_rd_out[32]
    DIRECTION OUTPUT ;
    USE SIGNAL ;
    SHAPE ABUTMENT ;
    PORT
      LAYER M3 ;
      RECT 115.443 0.000 115.461 0.054 ;
    END
  END rw0_rd_out[32]
  PIN rw0_rd_out[33]
    DIRECTION OUTPUT ;
    USE SIGNAL ;
    SHAPE ABUTMENT ;
    PORT
      LAYER M3 ;
      RECT 116.631 0.000 116.649 0.054 ;
    END
  END rw0_rd_out[33]
  PIN rw0_rd_out[34]
    DIRECTION OUTPUT ;
    USE SIGNAL ;
    SHAPE ABUTMENT ;
    PORT
      LAYER M3 ;
      RECT 117.819 0.000 117.837 0.054 ;
    END
  END rw0_rd_out[34]
  PIN rw0_rd_out[35]
    DIRECTION OUTPUT ;
    USE SIGNAL ;
    SHAPE ABUTMENT ;
    PORT
      LAYER M3 ;
      RECT 119.007 0.000 119.025 0.054 ;
    END
  END rw0_rd_out[35]
  PIN rw0_rd_out[36]
    DIRECTION OUTPUT ;
    USE SIGNAL ;
    SHAPE ABUTMENT ;
    PORT
      LAYER M3 ;
      RECT 120.195 0.000 120.213 0.054 ;
    END
  END rw0_rd_out[36]
  PIN rw0_rd_out[37]
    DIRECTION OUTPUT ;
    USE SIGNAL ;
    SHAPE ABUTMENT ;
    PORT
      LAYER M3 ;
      RECT 121.383 0.000 121.401 0.054 ;
    END
  END rw0_rd_out[37]
  PIN rw0_rd_out[38]
    DIRECTION OUTPUT ;
    USE SIGNAL ;
    SHAPE ABUTMENT ;
    PORT
      LAYER M3 ;
      RECT 122.571 0.000 122.589 0.054 ;
    END
  END rw0_rd_out[38]
  PIN rw0_rd_out[39]
    DIRECTION OUTPUT ;
    USE SIGNAL ;
    SHAPE ABUTMENT ;
    PORT
      LAYER M3 ;
      RECT 123.759 0.000 123.777 0.054 ;
    END
  END rw0_rd_out[39]
  PIN rw0_rd_out[40]
    DIRECTION OUTPUT ;
    USE SIGNAL ;
    SHAPE ABUTMENT ;
    PORT
      LAYER M3 ;
      RECT 124.947 0.000 124.965 0.054 ;
    END
  END rw0_rd_out[40]
  PIN rw0_rd_out[41]
    DIRECTION OUTPUT ;
    USE SIGNAL ;
    SHAPE ABUTMENT ;
    PORT
      LAYER M3 ;
      RECT 126.135 0.000 126.153 0.054 ;
    END
  END rw0_rd_out[41]
  PIN rw0_rd_out[42]
    DIRECTION OUTPUT ;
    USE SIGNAL ;
    SHAPE ABUTMENT ;
    PORT
      LAYER M3 ;
      RECT 127.323 0.000 127.341 0.054 ;
    END
  END rw0_rd_out[42]
  PIN rw0_rd_out[43]
    DIRECTION OUTPUT ;
    USE SIGNAL ;
    SHAPE ABUTMENT ;
    PORT
      LAYER M3 ;
      RECT 128.511 0.000 128.529 0.054 ;
    END
  END rw0_rd_out[43]
  PIN rw0_rd_out[44]
    DIRECTION OUTPUT ;
    USE SIGNAL ;
    SHAPE ABUTMENT ;
    PORT
      LAYER M3 ;
      RECT 129.699 0.000 129.717 0.054 ;
    END
  END rw0_rd_out[44]
  PIN rw0_rd_out[45]
    DIRECTION OUTPUT ;
    USE SIGNAL ;
    SHAPE ABUTMENT ;
    PORT
      LAYER M3 ;
      RECT 130.887 0.000 130.905 0.054 ;
    END
  END rw0_rd_out[45]
  PIN rw0_rd_out[46]
    DIRECTION OUTPUT ;
    USE SIGNAL ;
    SHAPE ABUTMENT ;
    PORT
      LAYER M3 ;
      RECT 132.075 0.000 132.093 0.054 ;
    END
  END rw0_rd_out[46]
  PIN rw0_rd_out[47]
    DIRECTION OUTPUT ;
    USE SIGNAL ;
    SHAPE ABUTMENT ;
    PORT
      LAYER M3 ;
      RECT 133.263 0.000 133.281 0.054 ;
    END
  END rw0_rd_out[47]
  PIN rw0_rd_out[48]
    DIRECTION OUTPUT ;
    USE SIGNAL ;
    SHAPE ABUTMENT ;
    PORT
      LAYER M3 ;
      RECT 134.451 0.000 134.469 0.054 ;
    END
  END rw0_rd_out[48]
  PIN rw0_rd_out[49]
    DIRECTION OUTPUT ;
    USE SIGNAL ;
    SHAPE ABUTMENT ;
    PORT
      LAYER M3 ;
      RECT 135.639 0.000 135.657 0.054 ;
    END
  END rw0_rd_out[49]
  PIN rw0_rd_out[50]
    DIRECTION OUTPUT ;
    USE SIGNAL ;
    SHAPE ABUTMENT ;
    PORT
      LAYER M3 ;
      RECT 136.827 0.000 136.845 0.054 ;
    END
  END rw0_rd_out[50]
  PIN rw0_rd_out[51]
    DIRECTION OUTPUT ;
    USE SIGNAL ;
    SHAPE ABUTMENT ;
    PORT
      LAYER M3 ;
      RECT 138.015 0.000 138.033 0.054 ;
    END
  END rw0_rd_out[51]
  PIN rw0_rd_out[52]
    DIRECTION OUTPUT ;
    USE SIGNAL ;
    SHAPE ABUTMENT ;
    PORT
      LAYER M3 ;
      RECT 139.203 0.000 139.221 0.054 ;
    END
  END rw0_rd_out[52]
  PIN rw0_rd_out[53]
    DIRECTION OUTPUT ;
    USE SIGNAL ;
    SHAPE ABUTMENT ;
    PORT
      LAYER M3 ;
      RECT 140.391 0.000 140.409 0.054 ;
    END
  END rw0_rd_out[53]
  PIN rw0_rd_out[54]
    DIRECTION OUTPUT ;
    USE SIGNAL ;
    SHAPE ABUTMENT ;
    PORT
      LAYER M3 ;
      RECT 141.579 0.000 141.597 0.054 ;
    END
  END rw0_rd_out[54]
  PIN rw0_rd_out[55]
    DIRECTION OUTPUT ;
    USE SIGNAL ;
    SHAPE ABUTMENT ;
    PORT
      LAYER M3 ;
      RECT 142.767 0.000 142.785 0.054 ;
    END
  END rw0_rd_out[55]
  PIN rw0_rd_out[56]
    DIRECTION OUTPUT ;
    USE SIGNAL ;
    SHAPE ABUTMENT ;
    PORT
      LAYER M3 ;
      RECT 143.955 0.000 143.973 0.054 ;
    END
  END rw0_rd_out[56]
  PIN rw0_rd_out[57]
    DIRECTION OUTPUT ;
    USE SIGNAL ;
    SHAPE ABUTMENT ;
    PORT
      LAYER M3 ;
      RECT 145.143 0.000 145.161 0.054 ;
    END
  END rw0_rd_out[57]
  PIN rw0_rd_out[58]
    DIRECTION OUTPUT ;
    USE SIGNAL ;
    SHAPE ABUTMENT ;
    PORT
      LAYER M3 ;
      RECT 146.331 0.000 146.349 0.054 ;
    END
  END rw0_rd_out[58]
  PIN rw0_rd_out[59]
    DIRECTION OUTPUT ;
    USE SIGNAL ;
    SHAPE ABUTMENT ;
    PORT
      LAYER M3 ;
      RECT 147.519 0.000 147.537 0.054 ;
    END
  END rw0_rd_out[59]
  PIN rw0_rd_out[60]
    DIRECTION OUTPUT ;
    USE SIGNAL ;
    SHAPE ABUTMENT ;
    PORT
      LAYER M3 ;
      RECT 148.707 0.000 148.725 0.054 ;
    END
  END rw0_rd_out[60]
  PIN rw0_rd_out[61]
    DIRECTION OUTPUT ;
    USE SIGNAL ;
    SHAPE ABUTMENT ;
    PORT
      LAYER M3 ;
      RECT 149.895 0.000 149.913 0.054 ;
    END
  END rw0_rd_out[61]
  PIN rw0_rd_out[62]
    DIRECTION OUTPUT ;
    USE SIGNAL ;
    SHAPE ABUTMENT ;
    PORT
      LAYER M3 ;
      RECT 151.083 0.000 151.101 0.054 ;
    END
  END rw0_rd_out[62]
  PIN rw0_rd_out[63]
    DIRECTION OUTPUT ;
    USE SIGNAL ;
    SHAPE ABUTMENT ;
    PORT
      LAYER M3 ;
      RECT 152.271 0.000 152.289 0.054 ;
    END
  END rw0_rd_out[63]
  PIN rw0_rd_out[64]
    DIRECTION OUTPUT ;
    USE SIGNAL ;
    SHAPE ABUTMENT ;
    PORT
      LAYER M3 ;
      RECT 153.459 0.000 153.477 0.054 ;
    END
  END rw0_rd_out[64]
  PIN rw0_rd_out[65]
    DIRECTION OUTPUT ;
    USE SIGNAL ;
    SHAPE ABUTMENT ;
    PORT
      LAYER M3 ;
      RECT 0.207 146.827 0.225 146.881 ;
    END
  END rw0_rd_out[65]
  PIN rw0_rd_out[66]
    DIRECTION OUTPUT ;
    USE SIGNAL ;
    SHAPE ABUTMENT ;
    PORT
      LAYER M3 ;
      RECT 1.971 146.827 1.989 146.881 ;
    END
  END rw0_rd_out[66]
  PIN rw0_rd_out[67]
    DIRECTION OUTPUT ;
    USE SIGNAL ;
    SHAPE ABUTMENT ;
    PORT
      LAYER M3 ;
      RECT 3.735 146.827 3.753 146.881 ;
    END
  END rw0_rd_out[67]
  PIN rw0_rd_out[68]
    DIRECTION OUTPUT ;
    USE SIGNAL ;
    SHAPE ABUTMENT ;
    PORT
      LAYER M3 ;
      RECT 5.499 146.827 5.517 146.881 ;
    END
  END rw0_rd_out[68]
  PIN rw0_rd_out[69]
    DIRECTION OUTPUT ;
    USE SIGNAL ;
    SHAPE ABUTMENT ;
    PORT
      LAYER M3 ;
      RECT 7.263 146.827 7.281 146.881 ;
    END
  END rw0_rd_out[69]
  PIN rw0_rd_out[70]
    DIRECTION OUTPUT ;
    USE SIGNAL ;
    SHAPE ABUTMENT ;
    PORT
      LAYER M3 ;
      RECT 9.027 146.827 9.045 146.881 ;
    END
  END rw0_rd_out[70]
  PIN rw0_rd_out[71]
    DIRECTION OUTPUT ;
    USE SIGNAL ;
    SHAPE ABUTMENT ;
    PORT
      LAYER M3 ;
      RECT 10.791 146.827 10.809 146.881 ;
    END
  END rw0_rd_out[71]
  PIN rw0_rd_out[72]
    DIRECTION OUTPUT ;
    USE SIGNAL ;
    SHAPE ABUTMENT ;
    PORT
      LAYER M3 ;
      RECT 12.555 146.827 12.573 146.881 ;
    END
  END rw0_rd_out[72]
  PIN rw0_rd_out[73]
    DIRECTION OUTPUT ;
    USE SIGNAL ;
    SHAPE ABUTMENT ;
    PORT
      LAYER M3 ;
      RECT 14.319 146.827 14.337 146.881 ;
    END
  END rw0_rd_out[73]
  PIN rw0_rd_out[74]
    DIRECTION OUTPUT ;
    USE SIGNAL ;
    SHAPE ABUTMENT ;
    PORT
      LAYER M3 ;
      RECT 16.083 146.827 16.101 146.881 ;
    END
  END rw0_rd_out[74]
  PIN rw0_rd_out[75]
    DIRECTION OUTPUT ;
    USE SIGNAL ;
    SHAPE ABUTMENT ;
    PORT
      LAYER M3 ;
      RECT 17.847 146.827 17.865 146.881 ;
    END
  END rw0_rd_out[75]
  PIN rw0_rd_out[76]
    DIRECTION OUTPUT ;
    USE SIGNAL ;
    SHAPE ABUTMENT ;
    PORT
      LAYER M3 ;
      RECT 19.611 146.827 19.629 146.881 ;
    END
  END rw0_rd_out[76]
  PIN rw0_rd_out[77]
    DIRECTION OUTPUT ;
    USE SIGNAL ;
    SHAPE ABUTMENT ;
    PORT
      LAYER M3 ;
      RECT 21.375 146.827 21.393 146.881 ;
    END
  END rw0_rd_out[77]
  PIN rw0_rd_out[78]
    DIRECTION OUTPUT ;
    USE SIGNAL ;
    SHAPE ABUTMENT ;
    PORT
      LAYER M3 ;
      RECT 23.139 146.827 23.157 146.881 ;
    END
  END rw0_rd_out[78]
  PIN rw0_rd_out[79]
    DIRECTION OUTPUT ;
    USE SIGNAL ;
    SHAPE ABUTMENT ;
    PORT
      LAYER M3 ;
      RECT 24.903 146.827 24.921 146.881 ;
    END
  END rw0_rd_out[79]
  PIN rw0_rd_out[80]
    DIRECTION OUTPUT ;
    USE SIGNAL ;
    SHAPE ABUTMENT ;
    PORT
      LAYER M3 ;
      RECT 26.667 146.827 26.685 146.881 ;
    END
  END rw0_rd_out[80]
  PIN rw0_rd_out[81]
    DIRECTION OUTPUT ;
    USE SIGNAL ;
    SHAPE ABUTMENT ;
    PORT
      LAYER M3 ;
      RECT 28.431 146.827 28.449 146.881 ;
    END
  END rw0_rd_out[81]
  PIN rw0_rd_out[82]
    DIRECTION OUTPUT ;
    USE SIGNAL ;
    SHAPE ABUTMENT ;
    PORT
      LAYER M3 ;
      RECT 30.195 146.827 30.213 146.881 ;
    END
  END rw0_rd_out[82]
  PIN rw0_rd_out[83]
    DIRECTION OUTPUT ;
    USE SIGNAL ;
    SHAPE ABUTMENT ;
    PORT
      LAYER M3 ;
      RECT 31.959 146.827 31.977 146.881 ;
    END
  END rw0_rd_out[83]
  PIN rw0_rd_out[84]
    DIRECTION OUTPUT ;
    USE SIGNAL ;
    SHAPE ABUTMENT ;
    PORT
      LAYER M3 ;
      RECT 33.723 146.827 33.741 146.881 ;
    END
  END rw0_rd_out[84]
  PIN rw0_rd_out[85]
    DIRECTION OUTPUT ;
    USE SIGNAL ;
    SHAPE ABUTMENT ;
    PORT
      LAYER M3 ;
      RECT 35.487 146.827 35.505 146.881 ;
    END
  END rw0_rd_out[85]
  PIN rw0_rd_out[86]
    DIRECTION OUTPUT ;
    USE SIGNAL ;
    SHAPE ABUTMENT ;
    PORT
      LAYER M3 ;
      RECT 37.251 146.827 37.269 146.881 ;
    END
  END rw0_rd_out[86]
  PIN rw0_rd_out[87]
    DIRECTION OUTPUT ;
    USE SIGNAL ;
    SHAPE ABUTMENT ;
    PORT
      LAYER M3 ;
      RECT 39.015 146.827 39.033 146.881 ;
    END
  END rw0_rd_out[87]
  PIN rw0_rd_out[88]
    DIRECTION OUTPUT ;
    USE SIGNAL ;
    SHAPE ABUTMENT ;
    PORT
      LAYER M3 ;
      RECT 40.779 146.827 40.797 146.881 ;
    END
  END rw0_rd_out[88]
  PIN rw0_rd_out[89]
    DIRECTION OUTPUT ;
    USE SIGNAL ;
    SHAPE ABUTMENT ;
    PORT
      LAYER M3 ;
      RECT 42.543 146.827 42.561 146.881 ;
    END
  END rw0_rd_out[89]
  PIN rw0_rd_out[90]
    DIRECTION OUTPUT ;
    USE SIGNAL ;
    SHAPE ABUTMENT ;
    PORT
      LAYER M3 ;
      RECT 44.307 146.827 44.325 146.881 ;
    END
  END rw0_rd_out[90]
  PIN rw0_rd_out[91]
    DIRECTION OUTPUT ;
    USE SIGNAL ;
    SHAPE ABUTMENT ;
    PORT
      LAYER M3 ;
      RECT 46.071 146.827 46.089 146.881 ;
    END
  END rw0_rd_out[91]
  PIN rw0_rd_out[92]
    DIRECTION OUTPUT ;
    USE SIGNAL ;
    SHAPE ABUTMENT ;
    PORT
      LAYER M3 ;
      RECT 47.835 146.827 47.853 146.881 ;
    END
  END rw0_rd_out[92]
  PIN rw0_rd_out[93]
    DIRECTION OUTPUT ;
    USE SIGNAL ;
    SHAPE ABUTMENT ;
    PORT
      LAYER M3 ;
      RECT 49.599 146.827 49.617 146.881 ;
    END
  END rw0_rd_out[93]
  PIN rw0_rd_out[94]
    DIRECTION OUTPUT ;
    USE SIGNAL ;
    SHAPE ABUTMENT ;
    PORT
      LAYER M3 ;
      RECT 51.363 146.827 51.381 146.881 ;
    END
  END rw0_rd_out[94]
  PIN rw0_rd_out[95]
    DIRECTION OUTPUT ;
    USE SIGNAL ;
    SHAPE ABUTMENT ;
    PORT
      LAYER M3 ;
      RECT 53.127 146.827 53.145 146.881 ;
    END
  END rw0_rd_out[95]
  PIN rw0_rd_out[96]
    DIRECTION OUTPUT ;
    USE SIGNAL ;
    SHAPE ABUTMENT ;
    PORT
      LAYER M3 ;
      RECT 54.891 146.827 54.909 146.881 ;
    END
  END rw0_rd_out[96]
  PIN rw0_rd_out[97]
    DIRECTION OUTPUT ;
    USE SIGNAL ;
    SHAPE ABUTMENT ;
    PORT
      LAYER M3 ;
      RECT 56.655 146.827 56.673 146.881 ;
    END
  END rw0_rd_out[97]
  PIN rw0_rd_out[98]
    DIRECTION OUTPUT ;
    USE SIGNAL ;
    SHAPE ABUTMENT ;
    PORT
      LAYER M3 ;
      RECT 58.419 146.827 58.437 146.881 ;
    END
  END rw0_rd_out[98]
  PIN rw0_rd_out[99]
    DIRECTION OUTPUT ;
    USE SIGNAL ;
    SHAPE ABUTMENT ;
    PORT
      LAYER M3 ;
      RECT 60.183 146.827 60.201 146.881 ;
    END
  END rw0_rd_out[99]
  PIN rw0_rd_out[100]
    DIRECTION OUTPUT ;
    USE SIGNAL ;
    SHAPE ABUTMENT ;
    PORT
      LAYER M3 ;
      RECT 61.947 146.827 61.965 146.881 ;
    END
  END rw0_rd_out[100]
  PIN rw0_rd_out[101]
    DIRECTION OUTPUT ;
    USE SIGNAL ;
    SHAPE ABUTMENT ;
    PORT
      LAYER M3 ;
      RECT 63.711 146.827 63.729 146.881 ;
    END
  END rw0_rd_out[101]
  PIN rw0_rd_out[102]
    DIRECTION OUTPUT ;
    USE SIGNAL ;
    SHAPE ABUTMENT ;
    PORT
      LAYER M3 ;
      RECT 65.475 146.827 65.493 146.881 ;
    END
  END rw0_rd_out[102]
  PIN rw0_rd_out[103]
    DIRECTION OUTPUT ;
    USE SIGNAL ;
    SHAPE ABUTMENT ;
    PORT
      LAYER M3 ;
      RECT 67.239 146.827 67.257 146.881 ;
    END
  END rw0_rd_out[103]
  PIN rw0_rd_out[104]
    DIRECTION OUTPUT ;
    USE SIGNAL ;
    SHAPE ABUTMENT ;
    PORT
      LAYER M3 ;
      RECT 69.003 146.827 69.021 146.881 ;
    END
  END rw0_rd_out[104]
  PIN rw0_rd_out[105]
    DIRECTION OUTPUT ;
    USE SIGNAL ;
    SHAPE ABUTMENT ;
    PORT
      LAYER M3 ;
      RECT 70.767 146.827 70.785 146.881 ;
    END
  END rw0_rd_out[105]
  PIN rw0_rd_out[106]
    DIRECTION OUTPUT ;
    USE SIGNAL ;
    SHAPE ABUTMENT ;
    PORT
      LAYER M3 ;
      RECT 72.531 146.827 72.549 146.881 ;
    END
  END rw0_rd_out[106]
  PIN rw0_rd_out[107]
    DIRECTION OUTPUT ;
    USE SIGNAL ;
    SHAPE ABUTMENT ;
    PORT
      LAYER M3 ;
      RECT 74.295 146.827 74.313 146.881 ;
    END
  END rw0_rd_out[107]
  PIN rw0_rd_out[108]
    DIRECTION OUTPUT ;
    USE SIGNAL ;
    SHAPE ABUTMENT ;
    PORT
      LAYER M3 ;
      RECT 76.059 146.827 76.077 146.881 ;
    END
  END rw0_rd_out[108]
  PIN rw0_rd_out[109]
    DIRECTION OUTPUT ;
    USE SIGNAL ;
    SHAPE ABUTMENT ;
    PORT
      LAYER M3 ;
      RECT 77.823 146.827 77.841 146.881 ;
    END
  END rw0_rd_out[109]
  PIN rw0_rd_out[110]
    DIRECTION OUTPUT ;
    USE SIGNAL ;
    SHAPE ABUTMENT ;
    PORT
      LAYER M3 ;
      RECT 79.587 146.827 79.605 146.881 ;
    END
  END rw0_rd_out[110]
  PIN rw0_rd_out[111]
    DIRECTION OUTPUT ;
    USE SIGNAL ;
    SHAPE ABUTMENT ;
    PORT
      LAYER M3 ;
      RECT 81.351 146.827 81.369 146.881 ;
    END
  END rw0_rd_out[111]
  PIN rw0_rd_out[112]
    DIRECTION OUTPUT ;
    USE SIGNAL ;
    SHAPE ABUTMENT ;
    PORT
      LAYER M3 ;
      RECT 83.115 146.827 83.133 146.881 ;
    END
  END rw0_rd_out[112]
  PIN rw0_rd_out[113]
    DIRECTION OUTPUT ;
    USE SIGNAL ;
    SHAPE ABUTMENT ;
    PORT
      LAYER M3 ;
      RECT 84.879 146.827 84.897 146.881 ;
    END
  END rw0_rd_out[113]
  PIN rw0_rd_out[114]
    DIRECTION OUTPUT ;
    USE SIGNAL ;
    SHAPE ABUTMENT ;
    PORT
      LAYER M3 ;
      RECT 86.643 146.827 86.661 146.881 ;
    END
  END rw0_rd_out[114]
  PIN rw0_rd_out[115]
    DIRECTION OUTPUT ;
    USE SIGNAL ;
    SHAPE ABUTMENT ;
    PORT
      LAYER M3 ;
      RECT 88.407 146.827 88.425 146.881 ;
    END
  END rw0_rd_out[115]
  PIN rw0_rd_out[116]
    DIRECTION OUTPUT ;
    USE SIGNAL ;
    SHAPE ABUTMENT ;
    PORT
      LAYER M3 ;
      RECT 90.171 146.827 90.189 146.881 ;
    END
  END rw0_rd_out[116]
  PIN rw0_rd_out[117]
    DIRECTION OUTPUT ;
    USE SIGNAL ;
    SHAPE ABUTMENT ;
    PORT
      LAYER M3 ;
      RECT 91.935 146.827 91.953 146.881 ;
    END
  END rw0_rd_out[117]
  PIN rw0_rd_out[118]
    DIRECTION OUTPUT ;
    USE SIGNAL ;
    SHAPE ABUTMENT ;
    PORT
      LAYER M3 ;
      RECT 93.699 146.827 93.717 146.881 ;
    END
  END rw0_rd_out[118]
  PIN rw0_rd_out[119]
    DIRECTION OUTPUT ;
    USE SIGNAL ;
    SHAPE ABUTMENT ;
    PORT
      LAYER M3 ;
      RECT 95.463 146.827 95.481 146.881 ;
    END
  END rw0_rd_out[119]
  PIN rw0_rd_out[120]
    DIRECTION OUTPUT ;
    USE SIGNAL ;
    SHAPE ABUTMENT ;
    PORT
      LAYER M3 ;
      RECT 97.227 146.827 97.245 146.881 ;
    END
  END rw0_rd_out[120]
  PIN rw0_rd_out[121]
    DIRECTION OUTPUT ;
    USE SIGNAL ;
    SHAPE ABUTMENT ;
    PORT
      LAYER M3 ;
      RECT 98.991 146.827 99.009 146.881 ;
    END
  END rw0_rd_out[121]
  PIN rw0_rd_out[122]
    DIRECTION OUTPUT ;
    USE SIGNAL ;
    SHAPE ABUTMENT ;
    PORT
      LAYER M3 ;
      RECT 100.755 146.827 100.773 146.881 ;
    END
  END rw0_rd_out[122]
  PIN rw0_rd_out[123]
    DIRECTION OUTPUT ;
    USE SIGNAL ;
    SHAPE ABUTMENT ;
    PORT
      LAYER M3 ;
      RECT 102.519 146.827 102.537 146.881 ;
    END
  END rw0_rd_out[123]
  PIN rw0_rd_out[124]
    DIRECTION OUTPUT ;
    USE SIGNAL ;
    SHAPE ABUTMENT ;
    PORT
      LAYER M3 ;
      RECT 104.283 146.827 104.301 146.881 ;
    END
  END rw0_rd_out[124]
  PIN rw0_rd_out[125]
    DIRECTION OUTPUT ;
    USE SIGNAL ;
    SHAPE ABUTMENT ;
    PORT
      LAYER M3 ;
      RECT 106.047 146.827 106.065 146.881 ;
    END
  END rw0_rd_out[125]
  PIN rw0_rd_out[126]
    DIRECTION OUTPUT ;
    USE SIGNAL ;
    SHAPE ABUTMENT ;
    PORT
      LAYER M3 ;
      RECT 107.811 146.827 107.829 146.881 ;
    END
  END rw0_rd_out[126]
  PIN rw0_rd_out[127]
    DIRECTION OUTPUT ;
    USE SIGNAL ;
    SHAPE ABUTMENT ;
    PORT
      LAYER M3 ;
      RECT 109.575 146.827 109.593 146.881 ;
    END
  END rw0_rd_out[127]
  PIN rw0_rd_out[128]
    DIRECTION OUTPUT ;
    USE SIGNAL ;
    SHAPE ABUTMENT ;
    PORT
      LAYER M3 ;
      RECT 111.339 146.827 111.357 146.881 ;
    END
  END rw0_rd_out[128]
  PIN rw0_rd_out[129]
    DIRECTION OUTPUT ;
    USE SIGNAL ;
    SHAPE ABUTMENT ;
    PORT
      LAYER M3 ;
      RECT 113.103 146.827 113.121 146.881 ;
    END
  END rw0_rd_out[129]
  PIN r0_rd_out[0]
    DIRECTION OUTPUT ;
    USE SIGNAL ;
    SHAPE ABUTMENT ;
    PORT
      LAYER M3 ;
      RECT 154.647 0.000 154.665 0.054 ;
    END
  END r0_rd_out[0]
  PIN r0_rd_out[1]
    DIRECTION OUTPUT ;
    USE SIGNAL ;
    SHAPE ABUTMENT ;
    PORT
      LAYER M3 ;
      RECT 155.835 0.000 155.853 0.054 ;
    END
  END r0_rd_out[1]
  PIN r0_rd_out[2]
    DIRECTION OUTPUT ;
    USE SIGNAL ;
    SHAPE ABUTMENT ;
    PORT
      LAYER M3 ;
      RECT 157.023 0.000 157.041 0.054 ;
    END
  END r0_rd_out[2]
  PIN r0_rd_out[3]
    DIRECTION OUTPUT ;
    USE SIGNAL ;
    SHAPE ABUTMENT ;
    PORT
      LAYER M3 ;
      RECT 158.211 0.000 158.229 0.054 ;
    END
  END r0_rd_out[3]
  PIN r0_rd_out[4]
    DIRECTION OUTPUT ;
    USE SIGNAL ;
    SHAPE ABUTMENT ;
    PORT
      LAYER M3 ;
      RECT 159.399 0.000 159.417 0.054 ;
    END
  END r0_rd_out[4]
  PIN r0_rd_out[5]
    DIRECTION OUTPUT ;
    USE SIGNAL ;
    SHAPE ABUTMENT ;
    PORT
      LAYER M3 ;
      RECT 160.587 0.000 160.605 0.054 ;
    END
  END r0_rd_out[5]
  PIN r0_rd_out[6]
    DIRECTION OUTPUT ;
    USE SIGNAL ;
    SHAPE ABUTMENT ;
    PORT
      LAYER M3 ;
      RECT 161.775 0.000 161.793 0.054 ;
    END
  END r0_rd_out[6]
  PIN r0_rd_out[7]
    DIRECTION OUTPUT ;
    USE SIGNAL ;
    SHAPE ABUTMENT ;
    PORT
      LAYER M3 ;
      RECT 162.963 0.000 162.981 0.054 ;
    END
  END r0_rd_out[7]
  PIN r0_rd_out[8]
    DIRECTION OUTPUT ;
    USE SIGNAL ;
    SHAPE ABUTMENT ;
    PORT
      LAYER M3 ;
      RECT 164.151 0.000 164.169 0.054 ;
    END
  END r0_rd_out[8]
  PIN r0_rd_out[9]
    DIRECTION OUTPUT ;
    USE SIGNAL ;
    SHAPE ABUTMENT ;
    PORT
      LAYER M3 ;
      RECT 165.339 0.000 165.357 0.054 ;
    END
  END r0_rd_out[9]
  PIN r0_rd_out[10]
    DIRECTION OUTPUT ;
    USE SIGNAL ;
    SHAPE ABUTMENT ;
    PORT
      LAYER M3 ;
      RECT 166.527 0.000 166.545 0.054 ;
    END
  END r0_rd_out[10]
  PIN r0_rd_out[11]
    DIRECTION OUTPUT ;
    USE SIGNAL ;
    SHAPE ABUTMENT ;
    PORT
      LAYER M3 ;
      RECT 167.715 0.000 167.733 0.054 ;
    END
  END r0_rd_out[11]
  PIN r0_rd_out[12]
    DIRECTION OUTPUT ;
    USE SIGNAL ;
    SHAPE ABUTMENT ;
    PORT
      LAYER M3 ;
      RECT 168.903 0.000 168.921 0.054 ;
    END
  END r0_rd_out[12]
  PIN r0_rd_out[13]
    DIRECTION OUTPUT ;
    USE SIGNAL ;
    SHAPE ABUTMENT ;
    PORT
      LAYER M3 ;
      RECT 170.091 0.000 170.109 0.054 ;
    END
  END r0_rd_out[13]
  PIN r0_rd_out[14]
    DIRECTION OUTPUT ;
    USE SIGNAL ;
    SHAPE ABUTMENT ;
    PORT
      LAYER M3 ;
      RECT 171.279 0.000 171.297 0.054 ;
    END
  END r0_rd_out[14]
  PIN r0_rd_out[15]
    DIRECTION OUTPUT ;
    USE SIGNAL ;
    SHAPE ABUTMENT ;
    PORT
      LAYER M3 ;
      RECT 172.467 0.000 172.485 0.054 ;
    END
  END r0_rd_out[15]
  PIN r0_rd_out[16]
    DIRECTION OUTPUT ;
    USE SIGNAL ;
    SHAPE ABUTMENT ;
    PORT
      LAYER M3 ;
      RECT 173.655 0.000 173.673 0.054 ;
    END
  END r0_rd_out[16]
  PIN r0_rd_out[17]
    DIRECTION OUTPUT ;
    USE SIGNAL ;
    SHAPE ABUTMENT ;
    PORT
      LAYER M3 ;
      RECT 174.843 0.000 174.861 0.054 ;
    END
  END r0_rd_out[17]
  PIN r0_rd_out[18]
    DIRECTION OUTPUT ;
    USE SIGNAL ;
    SHAPE ABUTMENT ;
    PORT
      LAYER M3 ;
      RECT 176.031 0.000 176.049 0.054 ;
    END
  END r0_rd_out[18]
  PIN r0_rd_out[19]
    DIRECTION OUTPUT ;
    USE SIGNAL ;
    SHAPE ABUTMENT ;
    PORT
      LAYER M3 ;
      RECT 177.219 0.000 177.237 0.054 ;
    END
  END r0_rd_out[19]
  PIN r0_rd_out[20]
    DIRECTION OUTPUT ;
    USE SIGNAL ;
    SHAPE ABUTMENT ;
    PORT
      LAYER M3 ;
      RECT 178.407 0.000 178.425 0.054 ;
    END
  END r0_rd_out[20]
  PIN r0_rd_out[21]
    DIRECTION OUTPUT ;
    USE SIGNAL ;
    SHAPE ABUTMENT ;
    PORT
      LAYER M3 ;
      RECT 179.595 0.000 179.613 0.054 ;
    END
  END r0_rd_out[21]
  PIN r0_rd_out[22]
    DIRECTION OUTPUT ;
    USE SIGNAL ;
    SHAPE ABUTMENT ;
    PORT
      LAYER M3 ;
      RECT 180.783 0.000 180.801 0.054 ;
    END
  END r0_rd_out[22]
  PIN r0_rd_out[23]
    DIRECTION OUTPUT ;
    USE SIGNAL ;
    SHAPE ABUTMENT ;
    PORT
      LAYER M3 ;
      RECT 181.971 0.000 181.989 0.054 ;
    END
  END r0_rd_out[23]
  PIN r0_rd_out[24]
    DIRECTION OUTPUT ;
    USE SIGNAL ;
    SHAPE ABUTMENT ;
    PORT
      LAYER M3 ;
      RECT 183.159 0.000 183.177 0.054 ;
    END
  END r0_rd_out[24]
  PIN r0_rd_out[25]
    DIRECTION OUTPUT ;
    USE SIGNAL ;
    SHAPE ABUTMENT ;
    PORT
      LAYER M3 ;
      RECT 184.347 0.000 184.365 0.054 ;
    END
  END r0_rd_out[25]
  PIN r0_rd_out[26]
    DIRECTION OUTPUT ;
    USE SIGNAL ;
    SHAPE ABUTMENT ;
    PORT
      LAYER M3 ;
      RECT 185.535 0.000 185.553 0.054 ;
    END
  END r0_rd_out[26]
  PIN r0_rd_out[27]
    DIRECTION OUTPUT ;
    USE SIGNAL ;
    SHAPE ABUTMENT ;
    PORT
      LAYER M3 ;
      RECT 186.723 0.000 186.741 0.054 ;
    END
  END r0_rd_out[27]
  PIN r0_rd_out[28]
    DIRECTION OUTPUT ;
    USE SIGNAL ;
    SHAPE ABUTMENT ;
    PORT
      LAYER M3 ;
      RECT 187.911 0.000 187.929 0.054 ;
    END
  END r0_rd_out[28]
  PIN r0_rd_out[29]
    DIRECTION OUTPUT ;
    USE SIGNAL ;
    SHAPE ABUTMENT ;
    PORT
      LAYER M3 ;
      RECT 189.099 0.000 189.117 0.054 ;
    END
  END r0_rd_out[29]
  PIN r0_rd_out[30]
    DIRECTION OUTPUT ;
    USE SIGNAL ;
    SHAPE ABUTMENT ;
    PORT
      LAYER M3 ;
      RECT 190.287 0.000 190.305 0.054 ;
    END
  END r0_rd_out[30]
  PIN r0_rd_out[31]
    DIRECTION OUTPUT ;
    USE SIGNAL ;
    SHAPE ABUTMENT ;
    PORT
      LAYER M3 ;
      RECT 191.475 0.000 191.493 0.054 ;
    END
  END r0_rd_out[31]
  PIN r0_rd_out[32]
    DIRECTION OUTPUT ;
    USE SIGNAL ;
    SHAPE ABUTMENT ;
    PORT
      LAYER M3 ;
      RECT 192.663 0.000 192.681 0.054 ;
    END
  END r0_rd_out[32]
  PIN r0_rd_out[33]
    DIRECTION OUTPUT ;
    USE SIGNAL ;
    SHAPE ABUTMENT ;
    PORT
      LAYER M3 ;
      RECT 193.851 0.000 193.869 0.054 ;
    END
  END r0_rd_out[33]
  PIN r0_rd_out[34]
    DIRECTION OUTPUT ;
    USE SIGNAL ;
    SHAPE ABUTMENT ;
    PORT
      LAYER M3 ;
      RECT 195.039 0.000 195.057 0.054 ;
    END
  END r0_rd_out[34]
  PIN r0_rd_out[35]
    DIRECTION OUTPUT ;
    USE SIGNAL ;
    SHAPE ABUTMENT ;
    PORT
      LAYER M3 ;
      RECT 196.227 0.000 196.245 0.054 ;
    END
  END r0_rd_out[35]
  PIN r0_rd_out[36]
    DIRECTION OUTPUT ;
    USE SIGNAL ;
    SHAPE ABUTMENT ;
    PORT
      LAYER M3 ;
      RECT 197.415 0.000 197.433 0.054 ;
    END
  END r0_rd_out[36]
  PIN r0_rd_out[37]
    DIRECTION OUTPUT ;
    USE SIGNAL ;
    SHAPE ABUTMENT ;
    PORT
      LAYER M3 ;
      RECT 198.603 0.000 198.621 0.054 ;
    END
  END r0_rd_out[37]
  PIN r0_rd_out[38]
    DIRECTION OUTPUT ;
    USE SIGNAL ;
    SHAPE ABUTMENT ;
    PORT
      LAYER M3 ;
      RECT 199.791 0.000 199.809 0.054 ;
    END
  END r0_rd_out[38]
  PIN r0_rd_out[39]
    DIRECTION OUTPUT ;
    USE SIGNAL ;
    SHAPE ABUTMENT ;
    PORT
      LAYER M3 ;
      RECT 200.979 0.000 200.997 0.054 ;
    END
  END r0_rd_out[39]
  PIN r0_rd_out[40]
    DIRECTION OUTPUT ;
    USE SIGNAL ;
    SHAPE ABUTMENT ;
    PORT
      LAYER M3 ;
      RECT 202.167 0.000 202.185 0.054 ;
    END
  END r0_rd_out[40]
  PIN r0_rd_out[41]
    DIRECTION OUTPUT ;
    USE SIGNAL ;
    SHAPE ABUTMENT ;
    PORT
      LAYER M3 ;
      RECT 203.355 0.000 203.373 0.054 ;
    END
  END r0_rd_out[41]
  PIN r0_rd_out[42]
    DIRECTION OUTPUT ;
    USE SIGNAL ;
    SHAPE ABUTMENT ;
    PORT
      LAYER M3 ;
      RECT 204.543 0.000 204.561 0.054 ;
    END
  END r0_rd_out[42]
  PIN r0_rd_out[43]
    DIRECTION OUTPUT ;
    USE SIGNAL ;
    SHAPE ABUTMENT ;
    PORT
      LAYER M3 ;
      RECT 205.731 0.000 205.749 0.054 ;
    END
  END r0_rd_out[43]
  PIN r0_rd_out[44]
    DIRECTION OUTPUT ;
    USE SIGNAL ;
    SHAPE ABUTMENT ;
    PORT
      LAYER M3 ;
      RECT 206.919 0.000 206.937 0.054 ;
    END
  END r0_rd_out[44]
  PIN r0_rd_out[45]
    DIRECTION OUTPUT ;
    USE SIGNAL ;
    SHAPE ABUTMENT ;
    PORT
      LAYER M3 ;
      RECT 208.107 0.000 208.125 0.054 ;
    END
  END r0_rd_out[45]
  PIN r0_rd_out[46]
    DIRECTION OUTPUT ;
    USE SIGNAL ;
    SHAPE ABUTMENT ;
    PORT
      LAYER M3 ;
      RECT 209.295 0.000 209.313 0.054 ;
    END
  END r0_rd_out[46]
  PIN r0_rd_out[47]
    DIRECTION OUTPUT ;
    USE SIGNAL ;
    SHAPE ABUTMENT ;
    PORT
      LAYER M3 ;
      RECT 210.483 0.000 210.501 0.054 ;
    END
  END r0_rd_out[47]
  PIN r0_rd_out[48]
    DIRECTION OUTPUT ;
    USE SIGNAL ;
    SHAPE ABUTMENT ;
    PORT
      LAYER M3 ;
      RECT 211.671 0.000 211.689 0.054 ;
    END
  END r0_rd_out[48]
  PIN r0_rd_out[49]
    DIRECTION OUTPUT ;
    USE SIGNAL ;
    SHAPE ABUTMENT ;
    PORT
      LAYER M3 ;
      RECT 212.859 0.000 212.877 0.054 ;
    END
  END r0_rd_out[49]
  PIN r0_rd_out[50]
    DIRECTION OUTPUT ;
    USE SIGNAL ;
    SHAPE ABUTMENT ;
    PORT
      LAYER M3 ;
      RECT 214.047 0.000 214.065 0.054 ;
    END
  END r0_rd_out[50]
  PIN r0_rd_out[51]
    DIRECTION OUTPUT ;
    USE SIGNAL ;
    SHAPE ABUTMENT ;
    PORT
      LAYER M3 ;
      RECT 215.235 0.000 215.253 0.054 ;
    END
  END r0_rd_out[51]
  PIN r0_rd_out[52]
    DIRECTION OUTPUT ;
    USE SIGNAL ;
    SHAPE ABUTMENT ;
    PORT
      LAYER M3 ;
      RECT 216.423 0.000 216.441 0.054 ;
    END
  END r0_rd_out[52]
  PIN r0_rd_out[53]
    DIRECTION OUTPUT ;
    USE SIGNAL ;
    SHAPE ABUTMENT ;
    PORT
      LAYER M3 ;
      RECT 217.611 0.000 217.629 0.054 ;
    END
  END r0_rd_out[53]
  PIN r0_rd_out[54]
    DIRECTION OUTPUT ;
    USE SIGNAL ;
    SHAPE ABUTMENT ;
    PORT
      LAYER M3 ;
      RECT 218.799 0.000 218.817 0.054 ;
    END
  END r0_rd_out[54]
  PIN r0_rd_out[55]
    DIRECTION OUTPUT ;
    USE SIGNAL ;
    SHAPE ABUTMENT ;
    PORT
      LAYER M3 ;
      RECT 219.987 0.000 220.005 0.054 ;
    END
  END r0_rd_out[55]
  PIN r0_rd_out[56]
    DIRECTION OUTPUT ;
    USE SIGNAL ;
    SHAPE ABUTMENT ;
    PORT
      LAYER M3 ;
      RECT 221.175 0.000 221.193 0.054 ;
    END
  END r0_rd_out[56]
  PIN r0_rd_out[57]
    DIRECTION OUTPUT ;
    USE SIGNAL ;
    SHAPE ABUTMENT ;
    PORT
      LAYER M3 ;
      RECT 222.363 0.000 222.381 0.054 ;
    END
  END r0_rd_out[57]
  PIN r0_rd_out[58]
    DIRECTION OUTPUT ;
    USE SIGNAL ;
    SHAPE ABUTMENT ;
    PORT
      LAYER M3 ;
      RECT 223.551 0.000 223.569 0.054 ;
    END
  END r0_rd_out[58]
  PIN r0_rd_out[59]
    DIRECTION OUTPUT ;
    USE SIGNAL ;
    SHAPE ABUTMENT ;
    PORT
      LAYER M3 ;
      RECT 224.739 0.000 224.757 0.054 ;
    END
  END r0_rd_out[59]
  PIN r0_rd_out[60]
    DIRECTION OUTPUT ;
    USE SIGNAL ;
    SHAPE ABUTMENT ;
    PORT
      LAYER M3 ;
      RECT 225.927 0.000 225.945 0.054 ;
    END
  END r0_rd_out[60]
  PIN r0_rd_out[61]
    DIRECTION OUTPUT ;
    USE SIGNAL ;
    SHAPE ABUTMENT ;
    PORT
      LAYER M3 ;
      RECT 227.115 0.000 227.133 0.054 ;
    END
  END r0_rd_out[61]
  PIN r0_rd_out[62]
    DIRECTION OUTPUT ;
    USE SIGNAL ;
    SHAPE ABUTMENT ;
    PORT
      LAYER M3 ;
      RECT 228.303 0.000 228.321 0.054 ;
    END
  END r0_rd_out[62]
  PIN r0_rd_out[63]
    DIRECTION OUTPUT ;
    USE SIGNAL ;
    SHAPE ABUTMENT ;
    PORT
      LAYER M3 ;
      RECT 229.491 0.000 229.509 0.054 ;
    END
  END r0_rd_out[63]
  PIN r0_rd_out[64]
    DIRECTION OUTPUT ;
    USE SIGNAL ;
    SHAPE ABUTMENT ;
    PORT
      LAYER M3 ;
      RECT 230.679 0.000 230.697 0.054 ;
    END
  END r0_rd_out[64]
  PIN r0_rd_out[65]
    DIRECTION OUTPUT ;
    USE SIGNAL ;
    SHAPE ABUTMENT ;
    PORT
      LAYER M3 ;
      RECT 114.867 146.827 114.885 146.881 ;
    END
  END r0_rd_out[65]
  PIN r0_rd_out[66]
    DIRECTION OUTPUT ;
    USE SIGNAL ;
    SHAPE ABUTMENT ;
    PORT
      LAYER M3 ;
      RECT 116.631 146.827 116.649 146.881 ;
    END
  END r0_rd_out[66]
  PIN r0_rd_out[67]
    DIRECTION OUTPUT ;
    USE SIGNAL ;
    SHAPE ABUTMENT ;
    PORT
      LAYER M3 ;
      RECT 118.395 146.827 118.413 146.881 ;
    END
  END r0_rd_out[67]
  PIN r0_rd_out[68]
    DIRECTION OUTPUT ;
    USE SIGNAL ;
    SHAPE ABUTMENT ;
    PORT
      LAYER M3 ;
      RECT 120.159 146.827 120.177 146.881 ;
    END
  END r0_rd_out[68]
  PIN r0_rd_out[69]
    DIRECTION OUTPUT ;
    USE SIGNAL ;
    SHAPE ABUTMENT ;
    PORT
      LAYER M3 ;
      RECT 121.923 146.827 121.941 146.881 ;
    END
  END r0_rd_out[69]
  PIN r0_rd_out[70]
    DIRECTION OUTPUT ;
    USE SIGNAL ;
    SHAPE ABUTMENT ;
    PORT
      LAYER M3 ;
      RECT 123.687 146.827 123.705 146.881 ;
    END
  END r0_rd_out[70]
  PIN r0_rd_out[71]
    DIRECTION OUTPUT ;
    USE SIGNAL ;
    SHAPE ABUTMENT ;
    PORT
      LAYER M3 ;
      RECT 125.451 146.827 125.469 146.881 ;
    END
  END r0_rd_out[71]
  PIN r0_rd_out[72]
    DIRECTION OUTPUT ;
    USE SIGNAL ;
    SHAPE ABUTMENT ;
    PORT
      LAYER M3 ;
      RECT 127.215 146.827 127.233 146.881 ;
    END
  END r0_rd_out[72]
  PIN r0_rd_out[73]
    DIRECTION OUTPUT ;
    USE SIGNAL ;
    SHAPE ABUTMENT ;
    PORT
      LAYER M3 ;
      RECT 128.979 146.827 128.997 146.881 ;
    END
  END r0_rd_out[73]
  PIN r0_rd_out[74]
    DIRECTION OUTPUT ;
    USE SIGNAL ;
    SHAPE ABUTMENT ;
    PORT
      LAYER M3 ;
      RECT 130.743 146.827 130.761 146.881 ;
    END
  END r0_rd_out[74]
  PIN r0_rd_out[75]
    DIRECTION OUTPUT ;
    USE SIGNAL ;
    SHAPE ABUTMENT ;
    PORT
      LAYER M3 ;
      RECT 132.507 146.827 132.525 146.881 ;
    END
  END r0_rd_out[75]
  PIN r0_rd_out[76]
    DIRECTION OUTPUT ;
    USE SIGNAL ;
    SHAPE ABUTMENT ;
    PORT
      LAYER M3 ;
      RECT 134.271 146.827 134.289 146.881 ;
    END
  END r0_rd_out[76]
  PIN r0_rd_out[77]
    DIRECTION OUTPUT ;
    USE SIGNAL ;
    SHAPE ABUTMENT ;
    PORT
      LAYER M3 ;
      RECT 136.035 146.827 136.053 146.881 ;
    END
  END r0_rd_out[77]
  PIN r0_rd_out[78]
    DIRECTION OUTPUT ;
    USE SIGNAL ;
    SHAPE ABUTMENT ;
    PORT
      LAYER M3 ;
      RECT 137.799 146.827 137.817 146.881 ;
    END
  END r0_rd_out[78]
  PIN r0_rd_out[79]
    DIRECTION OUTPUT ;
    USE SIGNAL ;
    SHAPE ABUTMENT ;
    PORT
      LAYER M3 ;
      RECT 139.563 146.827 139.581 146.881 ;
    END
  END r0_rd_out[79]
  PIN r0_rd_out[80]
    DIRECTION OUTPUT ;
    USE SIGNAL ;
    SHAPE ABUTMENT ;
    PORT
      LAYER M3 ;
      RECT 141.327 146.827 141.345 146.881 ;
    END
  END r0_rd_out[80]
  PIN r0_rd_out[81]
    DIRECTION OUTPUT ;
    USE SIGNAL ;
    SHAPE ABUTMENT ;
    PORT
      LAYER M3 ;
      RECT 143.091 146.827 143.109 146.881 ;
    END
  END r0_rd_out[81]
  PIN r0_rd_out[82]
    DIRECTION OUTPUT ;
    USE SIGNAL ;
    SHAPE ABUTMENT ;
    PORT
      LAYER M3 ;
      RECT 144.855 146.827 144.873 146.881 ;
    END
  END r0_rd_out[82]
  PIN r0_rd_out[83]
    DIRECTION OUTPUT ;
    USE SIGNAL ;
    SHAPE ABUTMENT ;
    PORT
      LAYER M3 ;
      RECT 146.619 146.827 146.637 146.881 ;
    END
  END r0_rd_out[83]
  PIN r0_rd_out[84]
    DIRECTION OUTPUT ;
    USE SIGNAL ;
    SHAPE ABUTMENT ;
    PORT
      LAYER M3 ;
      RECT 148.383 146.827 148.401 146.881 ;
    END
  END r0_rd_out[84]
  PIN r0_rd_out[85]
    DIRECTION OUTPUT ;
    USE SIGNAL ;
    SHAPE ABUTMENT ;
    PORT
      LAYER M3 ;
      RECT 150.147 146.827 150.165 146.881 ;
    END
  END r0_rd_out[85]
  PIN r0_rd_out[86]
    DIRECTION OUTPUT ;
    USE SIGNAL ;
    SHAPE ABUTMENT ;
    PORT
      LAYER M3 ;
      RECT 151.911 146.827 151.929 146.881 ;
    END
  END r0_rd_out[86]
  PIN r0_rd_out[87]
    DIRECTION OUTPUT ;
    USE SIGNAL ;
    SHAPE ABUTMENT ;
    PORT
      LAYER M3 ;
      RECT 153.675 146.827 153.693 146.881 ;
    END
  END r0_rd_out[87]
  PIN r0_rd_out[88]
    DIRECTION OUTPUT ;
    USE SIGNAL ;
    SHAPE ABUTMENT ;
    PORT
      LAYER M3 ;
      RECT 155.439 146.827 155.457 146.881 ;
    END
  END r0_rd_out[88]
  PIN r0_rd_out[89]
    DIRECTION OUTPUT ;
    USE SIGNAL ;
    SHAPE ABUTMENT ;
    PORT
      LAYER M3 ;
      RECT 157.203 146.827 157.221 146.881 ;
    END
  END r0_rd_out[89]
  PIN r0_rd_out[90]
    DIRECTION OUTPUT ;
    USE SIGNAL ;
    SHAPE ABUTMENT ;
    PORT
      LAYER M3 ;
      RECT 158.967 146.827 158.985 146.881 ;
    END
  END r0_rd_out[90]
  PIN r0_rd_out[91]
    DIRECTION OUTPUT ;
    USE SIGNAL ;
    SHAPE ABUTMENT ;
    PORT
      LAYER M3 ;
      RECT 160.731 146.827 160.749 146.881 ;
    END
  END r0_rd_out[91]
  PIN r0_rd_out[92]
    DIRECTION OUTPUT ;
    USE SIGNAL ;
    SHAPE ABUTMENT ;
    PORT
      LAYER M3 ;
      RECT 162.495 146.827 162.513 146.881 ;
    END
  END r0_rd_out[92]
  PIN r0_rd_out[93]
    DIRECTION OUTPUT ;
    USE SIGNAL ;
    SHAPE ABUTMENT ;
    PORT
      LAYER M3 ;
      RECT 164.259 146.827 164.277 146.881 ;
    END
  END r0_rd_out[93]
  PIN r0_rd_out[94]
    DIRECTION OUTPUT ;
    USE SIGNAL ;
    SHAPE ABUTMENT ;
    PORT
      LAYER M3 ;
      RECT 166.023 146.827 166.041 146.881 ;
    END
  END r0_rd_out[94]
  PIN r0_rd_out[95]
    DIRECTION OUTPUT ;
    USE SIGNAL ;
    SHAPE ABUTMENT ;
    PORT
      LAYER M3 ;
      RECT 167.787 146.827 167.805 146.881 ;
    END
  END r0_rd_out[95]
  PIN r0_rd_out[96]
    DIRECTION OUTPUT ;
    USE SIGNAL ;
    SHAPE ABUTMENT ;
    PORT
      LAYER M3 ;
      RECT 169.551 146.827 169.569 146.881 ;
    END
  END r0_rd_out[96]
  PIN r0_rd_out[97]
    DIRECTION OUTPUT ;
    USE SIGNAL ;
    SHAPE ABUTMENT ;
    PORT
      LAYER M3 ;
      RECT 171.315 146.827 171.333 146.881 ;
    END
  END r0_rd_out[97]
  PIN r0_rd_out[98]
    DIRECTION OUTPUT ;
    USE SIGNAL ;
    SHAPE ABUTMENT ;
    PORT
      LAYER M3 ;
      RECT 173.079 146.827 173.097 146.881 ;
    END
  END r0_rd_out[98]
  PIN r0_rd_out[99]
    DIRECTION OUTPUT ;
    USE SIGNAL ;
    SHAPE ABUTMENT ;
    PORT
      LAYER M3 ;
      RECT 174.843 146.827 174.861 146.881 ;
    END
  END r0_rd_out[99]
  PIN r0_rd_out[100]
    DIRECTION OUTPUT ;
    USE SIGNAL ;
    SHAPE ABUTMENT ;
    PORT
      LAYER M3 ;
      RECT 176.607 146.827 176.625 146.881 ;
    END
  END r0_rd_out[100]
  PIN r0_rd_out[101]
    DIRECTION OUTPUT ;
    USE SIGNAL ;
    SHAPE ABUTMENT ;
    PORT
      LAYER M3 ;
      RECT 178.371 146.827 178.389 146.881 ;
    END
  END r0_rd_out[101]
  PIN r0_rd_out[102]
    DIRECTION OUTPUT ;
    USE SIGNAL ;
    SHAPE ABUTMENT ;
    PORT
      LAYER M3 ;
      RECT 180.135 146.827 180.153 146.881 ;
    END
  END r0_rd_out[102]
  PIN r0_rd_out[103]
    DIRECTION OUTPUT ;
    USE SIGNAL ;
    SHAPE ABUTMENT ;
    PORT
      LAYER M3 ;
      RECT 181.899 146.827 181.917 146.881 ;
    END
  END r0_rd_out[103]
  PIN r0_rd_out[104]
    DIRECTION OUTPUT ;
    USE SIGNAL ;
    SHAPE ABUTMENT ;
    PORT
      LAYER M3 ;
      RECT 183.663 146.827 183.681 146.881 ;
    END
  END r0_rd_out[104]
  PIN r0_rd_out[105]
    DIRECTION OUTPUT ;
    USE SIGNAL ;
    SHAPE ABUTMENT ;
    PORT
      LAYER M3 ;
      RECT 185.427 146.827 185.445 146.881 ;
    END
  END r0_rd_out[105]
  PIN r0_rd_out[106]
    DIRECTION OUTPUT ;
    USE SIGNAL ;
    SHAPE ABUTMENT ;
    PORT
      LAYER M3 ;
      RECT 187.191 146.827 187.209 146.881 ;
    END
  END r0_rd_out[106]
  PIN r0_rd_out[107]
    DIRECTION OUTPUT ;
    USE SIGNAL ;
    SHAPE ABUTMENT ;
    PORT
      LAYER M3 ;
      RECT 188.955 146.827 188.973 146.881 ;
    END
  END r0_rd_out[107]
  PIN r0_rd_out[108]
    DIRECTION OUTPUT ;
    USE SIGNAL ;
    SHAPE ABUTMENT ;
    PORT
      LAYER M3 ;
      RECT 190.719 146.827 190.737 146.881 ;
    END
  END r0_rd_out[108]
  PIN r0_rd_out[109]
    DIRECTION OUTPUT ;
    USE SIGNAL ;
    SHAPE ABUTMENT ;
    PORT
      LAYER M3 ;
      RECT 192.483 146.827 192.501 146.881 ;
    END
  END r0_rd_out[109]
  PIN r0_rd_out[110]
    DIRECTION OUTPUT ;
    USE SIGNAL ;
    SHAPE ABUTMENT ;
    PORT
      LAYER M3 ;
      RECT 194.247 146.827 194.265 146.881 ;
    END
  END r0_rd_out[110]
  PIN r0_rd_out[111]
    DIRECTION OUTPUT ;
    USE SIGNAL ;
    SHAPE ABUTMENT ;
    PORT
      LAYER M3 ;
      RECT 196.011 146.827 196.029 146.881 ;
    END
  END r0_rd_out[111]
  PIN r0_rd_out[112]
    DIRECTION OUTPUT ;
    USE SIGNAL ;
    SHAPE ABUTMENT ;
    PORT
      LAYER M3 ;
      RECT 197.775 146.827 197.793 146.881 ;
    END
  END r0_rd_out[112]
  PIN r0_rd_out[113]
    DIRECTION OUTPUT ;
    USE SIGNAL ;
    SHAPE ABUTMENT ;
    PORT
      LAYER M3 ;
      RECT 199.539 146.827 199.557 146.881 ;
    END
  END r0_rd_out[113]
  PIN r0_rd_out[114]
    DIRECTION OUTPUT ;
    USE SIGNAL ;
    SHAPE ABUTMENT ;
    PORT
      LAYER M3 ;
      RECT 201.303 146.827 201.321 146.881 ;
    END
  END r0_rd_out[114]
  PIN r0_rd_out[115]
    DIRECTION OUTPUT ;
    USE SIGNAL ;
    SHAPE ABUTMENT ;
    PORT
      LAYER M3 ;
      RECT 203.067 146.827 203.085 146.881 ;
    END
  END r0_rd_out[115]
  PIN r0_rd_out[116]
    DIRECTION OUTPUT ;
    USE SIGNAL ;
    SHAPE ABUTMENT ;
    PORT
      LAYER M3 ;
      RECT 204.831 146.827 204.849 146.881 ;
    END
  END r0_rd_out[116]
  PIN r0_rd_out[117]
    DIRECTION OUTPUT ;
    USE SIGNAL ;
    SHAPE ABUTMENT ;
    PORT
      LAYER M3 ;
      RECT 206.595 146.827 206.613 146.881 ;
    END
  END r0_rd_out[117]
  PIN r0_rd_out[118]
    DIRECTION OUTPUT ;
    USE SIGNAL ;
    SHAPE ABUTMENT ;
    PORT
      LAYER M3 ;
      RECT 208.359 146.827 208.377 146.881 ;
    END
  END r0_rd_out[118]
  PIN r0_rd_out[119]
    DIRECTION OUTPUT ;
    USE SIGNAL ;
    SHAPE ABUTMENT ;
    PORT
      LAYER M3 ;
      RECT 210.123 146.827 210.141 146.881 ;
    END
  END r0_rd_out[119]
  PIN r0_rd_out[120]
    DIRECTION OUTPUT ;
    USE SIGNAL ;
    SHAPE ABUTMENT ;
    PORT
      LAYER M3 ;
      RECT 211.887 146.827 211.905 146.881 ;
    END
  END r0_rd_out[120]
  PIN r0_rd_out[121]
    DIRECTION OUTPUT ;
    USE SIGNAL ;
    SHAPE ABUTMENT ;
    PORT
      LAYER M3 ;
      RECT 213.651 146.827 213.669 146.881 ;
    END
  END r0_rd_out[121]
  PIN r0_rd_out[122]
    DIRECTION OUTPUT ;
    USE SIGNAL ;
    SHAPE ABUTMENT ;
    PORT
      LAYER M3 ;
      RECT 215.415 146.827 215.433 146.881 ;
    END
  END r0_rd_out[122]
  PIN r0_rd_out[123]
    DIRECTION OUTPUT ;
    USE SIGNAL ;
    SHAPE ABUTMENT ;
    PORT
      LAYER M3 ;
      RECT 217.179 146.827 217.197 146.881 ;
    END
  END r0_rd_out[123]
  PIN r0_rd_out[124]
    DIRECTION OUTPUT ;
    USE SIGNAL ;
    SHAPE ABUTMENT ;
    PORT
      LAYER M3 ;
      RECT 218.943 146.827 218.961 146.881 ;
    END
  END r0_rd_out[124]
  PIN r0_rd_out[125]
    DIRECTION OUTPUT ;
    USE SIGNAL ;
    SHAPE ABUTMENT ;
    PORT
      LAYER M3 ;
      RECT 220.707 146.827 220.725 146.881 ;
    END
  END r0_rd_out[125]
  PIN r0_rd_out[126]
    DIRECTION OUTPUT ;
    USE SIGNAL ;
    SHAPE ABUTMENT ;
    PORT
      LAYER M3 ;
      RECT 222.471 146.827 222.489 146.881 ;
    END
  END r0_rd_out[126]
  PIN r0_rd_out[127]
    DIRECTION OUTPUT ;
    USE SIGNAL ;
    SHAPE ABUTMENT ;
    PORT
      LAYER M3 ;
      RECT 224.235 146.827 224.253 146.881 ;
    END
  END r0_rd_out[127]
  PIN r0_rd_out[128]
    DIRECTION OUTPUT ;
    USE SIGNAL ;
    SHAPE ABUTMENT ;
    PORT
      LAYER M3 ;
      RECT 225.999 146.827 226.017 146.881 ;
    END
  END r0_rd_out[128]
  PIN r0_rd_out[129]
    DIRECTION OUTPUT ;
    USE SIGNAL ;
    SHAPE ABUTMENT ;
    PORT
      LAYER M3 ;
      RECT 227.763 146.827 227.781 146.881 ;
    END
  END r0_rd_out[129]
  PIN rw0_addr_in[0]
    DIRECTION INPUT ;
    USE SIGNAL ;
    SHAPE ABUTMENT ;
    PORT
      LAYER M4 ;
      RECT 0.000 114.324 0.072 114.348 ;
    END
  END rw0_addr_in[0]
  PIN rw0_addr_in[1]
    DIRECTION INPUT ;
    USE SIGNAL ;
    SHAPE ABUTMENT ;
    PORT
      LAYER M4 ;
      RECT 0.000 117.780 0.072 117.804 ;
    END
  END rw0_addr_in[1]
  PIN rw0_addr_in[2]
    DIRECTION INPUT ;
    USE SIGNAL ;
    SHAPE ABUTMENT ;
    PORT
      LAYER M4 ;
      RECT 0.000 121.236 0.072 121.260 ;
    END
  END rw0_addr_in[2]
  PIN rw0_addr_in[3]
    DIRECTION INPUT ;
    USE SIGNAL ;
    SHAPE ABUTMENT ;
    PORT
      LAYER M4 ;
      RECT 0.000 124.692 0.072 124.716 ;
    END
  END rw0_addr_in[3]
  PIN rw0_addr_in[4]
    DIRECTION INPUT ;
    USE SIGNAL ;
    SHAPE ABUTMENT ;
    PORT
      LAYER M4 ;
      RECT 0.000 128.148 0.072 128.172 ;
    END
  END rw0_addr_in[4]
  PIN rw0_addr_in[5]
    DIRECTION INPUT ;
    USE SIGNAL ;
    SHAPE ABUTMENT ;
    PORT
      LAYER M4 ;
      RECT 238.608 110.868 238.680 110.892 ;
    END
  END rw0_addr_in[5]
  PIN rw0_addr_in[6]
    DIRECTION INPUT ;
    USE SIGNAL ;
    SHAPE ABUTMENT ;
    PORT
      LAYER M4 ;
      RECT 238.608 114.324 238.680 114.348 ;
    END
  END rw0_addr_in[6]
  PIN rw0_addr_in[7]
    DIRECTION INPUT ;
    USE SIGNAL ;
    SHAPE ABUTMENT ;
    PORT
      LAYER M4 ;
      RECT 238.608 117.780 238.680 117.804 ;
    END
  END rw0_addr_in[7]
  PIN rw0_addr_in[8]
    DIRECTION INPUT ;
    USE SIGNAL ;
    SHAPE ABUTMENT ;
    PORT
      LAYER M4 ;
      RECT 238.608 121.236 238.680 121.260 ;
    END
  END rw0_addr_in[8]
  PIN r0_addr_in[0]
    DIRECTION INPUT ;
    USE SIGNAL ;
    SHAPE ABUTMENT ;
    PORT
      LAYER M4 ;
      RECT 0.000 131.604 0.072 131.628 ;
    END
  END r0_addr_in[0]
  PIN r0_addr_in[1]
    DIRECTION INPUT ;
    USE SIGNAL ;
    SHAPE ABUTMENT ;
    PORT
      LAYER M4 ;
      RECT 0.000 135.060 0.072 135.084 ;
    END
  END r0_addr_in[1]
  PIN r0_addr_in[2]
    DIRECTION INPUT ;
    USE SIGNAL ;
    SHAPE ABUTMENT ;
    PORT
      LAYER M4 ;
      RECT 0.000 138.516 0.072 138.540 ;
    END
  END r0_addr_in[2]
  PIN r0_addr_in[3]
    DIRECTION INPUT ;
    USE SIGNAL ;
    SHAPE ABUTMENT ;
    PORT
      LAYER M4 ;
      RECT 0.000 141.972 0.072 141.996 ;
    END
  END r0_addr_in[3]
  PIN r0_addr_in[4]
    DIRECTION INPUT ;
    USE SIGNAL ;
    SHAPE ABUTMENT ;
    PORT
      LAYER M4 ;
      RECT 0.000 145.428 0.072 145.452 ;
    END
  END r0_addr_in[4]
  PIN r0_addr_in[5]
    DIRECTION INPUT ;
    USE SIGNAL ;
    SHAPE ABUTMENT ;
    PORT
      LAYER M4 ;
      RECT 238.608 124.692 238.680 124.716 ;
    END
  END r0_addr_in[5]
  PIN r0_addr_in[6]
    DIRECTION INPUT ;
    USE SIGNAL ;
    SHAPE ABUTMENT ;
    PORT
      LAYER M4 ;
      RECT 238.608 128.148 238.680 128.172 ;
    END
  END r0_addr_in[6]
  PIN r0_addr_in[7]
    DIRECTION INPUT ;
    USE SIGNAL ;
    SHAPE ABUTMENT ;
    PORT
      LAYER M4 ;
      RECT 238.608 131.604 238.680 131.628 ;
    END
  END r0_addr_in[7]
  PIN r0_addr_in[8]
    DIRECTION INPUT ;
    USE SIGNAL ;
    SHAPE ABUTMENT ;
    PORT
      LAYER M4 ;
      RECT 238.608 135.060 238.680 135.084 ;
    END
  END r0_addr_in[8]
  PIN rw0_we_in
    DIRECTION INPUT ;
    USE SIGNAL ;
    SHAPE ABUTMENT ;
    PORT
      LAYER M3 ;
      RECT 229.527 146.827 229.545 146.881 ;
    END
  END rw0_we_in
  PIN rw0_ce_in
    DIRECTION INPUT ;
    USE SIGNAL ;
    SHAPE ABUTMENT ;
    PORT
      LAYER M3 ;
      RECT 231.291 146.827 231.309 146.881 ;
    END
  END rw0_ce_in
  PIN rw0_clk
    DIRECTION INPUT ;
    USE SIGNAL ;
    SHAPE ABUTMENT ;
    PORT
      LAYER M3 ;
      RECT 233.055 146.827 233.073 146.881 ;
    END
  END rw0_clk
  PIN r0_ce_in
    DIRECTION INPUT ;
    USE SIGNAL ;
    SHAPE ABUTMENT ;
    PORT
      LAYER M3 ;
      RECT 234.819 146.827 234.837 146.881 ;
    END
  END r0_ce_in
  PIN r0_clk
    DIRECTION INPUT ;
    USE SIGNAL ;
    SHAPE ABUTMENT ;
    PORT
      LAYER M3 ;
      RECT 236.583 146.827 236.601 146.881 ;
    END
  END r0_clk
  PIN VSS
    DIRECTION INOUT ;
    USE GROUND ;
    PORT
      LAYER M4 ;
      RECT 0.216 0.240 238.464 0.336 ;
      RECT 0.216 1.008 238.464 1.104 ;
      RECT 0.216 1.776 238.464 1.872 ;
      RECT 0.216 2.544 238.464 2.640 ;
      RECT 0.216 3.312 238.464 3.408 ;
      RECT 0.216 4.080 238.464 4.176 ;
      RECT 0.216 4.848 238.464 4.944 ;
      RECT 0.216 5.616 238.464 5.712 ;
      RECT 0.216 6.384 238.464 6.480 ;
      RECT 0.216 7.152 238.464 7.248 ;
      RECT 0.216 7.920 238.464 8.016 ;
      RECT 0.216 8.688 238.464 8.784 ;
      RECT 0.216 9.456 238.464 9.552 ;
      RECT 0.216 10.224 238.464 10.320 ;
      RECT 0.216 10.992 238.464 11.088 ;
      RECT 0.216 11.760 238.464 11.856 ;
      RECT 0.216 12.528 238.464 12.624 ;
      RECT 0.216 13.296 238.464 13.392 ;
      RECT 0.216 14.064 238.464 14.160 ;
      RECT 0.216 14.832 238.464 14.928 ;
      RECT 0.216 15.600 238.464 15.696 ;
      RECT 0.216 16.368 238.464 16.464 ;
      RECT 0.216 17.136 238.464 17.232 ;
      RECT 0.216 17.904 238.464 18.000 ;
      RECT 0.216 18.672 238.464 18.768 ;
      RECT 0.216 19.440 238.464 19.536 ;
      RECT 0.216 20.208 238.464 20.304 ;
      RECT 0.216 20.976 238.464 21.072 ;
      RECT 0.216 21.744 238.464 21.840 ;
      RECT 0.216 22.512 238.464 22.608 ;
      RECT 0.216 23.280 238.464 23.376 ;
      RECT 0.216 24.048 238.464 24.144 ;
      RECT 0.216 24.816 238.464 24.912 ;
      RECT 0.216 25.584 238.464 25.680 ;
      RECT 0.216 26.352 238.464 26.448 ;
      RECT 0.216 27.120 238.464 27.216 ;
      RECT 0.216 27.888 238.464 27.984 ;
      RECT 0.216 28.656 238.464 28.752 ;
      RECT 0.216 29.424 238.464 29.520 ;
      RECT 0.216 30.192 238.464 30.288 ;
      RECT 0.216 30.960 238.464 31.056 ;
      RECT 0.216 31.728 238.464 31.824 ;
      RECT 0.216 32.496 238.464 32.592 ;
      RECT 0.216 33.264 238.464 33.360 ;
      RECT 0.216 34.032 238.464 34.128 ;
      RECT 0.216 34.800 238.464 34.896 ;
      RECT 0.216 35.568 238.464 35.664 ;
      RECT 0.216 36.336 238.464 36.432 ;
      RECT 0.216 37.104 238.464 37.200 ;
      RECT 0.216 37.872 238.464 37.968 ;
      RECT 0.216 38.640 238.464 38.736 ;
      RECT 0.216 39.408 238.464 39.504 ;
      RECT 0.216 40.176 238.464 40.272 ;
      RECT 0.216 40.944 238.464 41.040 ;
      RECT 0.216 41.712 238.464 41.808 ;
      RECT 0.216 42.480 238.464 42.576 ;
      RECT 0.216 43.248 238.464 43.344 ;
      RECT 0.216 44.016 238.464 44.112 ;
      RECT 0.216 44.784 238.464 44.880 ;
      RECT 0.216 45.552 238.464 45.648 ;
      RECT 0.216 46.320 238.464 46.416 ;
      RECT 0.216 47.088 238.464 47.184 ;
      RECT 0.216 47.856 238.464 47.952 ;
      RECT 0.216 48.624 238.464 48.720 ;
      RECT 0.216 49.392 238.464 49.488 ;
      RECT 0.216 50.160 238.464 50.256 ;
      RECT 0.216 50.928 238.464 51.024 ;
      RECT 0.216 51.696 238.464 51.792 ;
      RECT 0.216 52.464 238.464 52.560 ;
      RECT 0.216 53.232 238.464 53.328 ;
      RECT 0.216 54.000 238.464 54.096 ;
      RECT 0.216 54.768 238.464 54.864 ;
      RECT 0.216 55.536 238.464 55.632 ;
      RECT 0.216 56.304 238.464 56.400 ;
      RECT 0.216 57.072 238.464 57.168 ;
      RECT 0.216 57.840 238.464 57.936 ;
      RECT 0.216 58.608 238.464 58.704 ;
      RECT 0.216 59.376 238.464 59.472 ;
      RECT 0.216 60.144 238.464 60.240 ;
      RECT 0.216 60.912 238.464 61.008 ;
      RECT 0.216 61.680 238.464 61.776 ;
      RECT 0.216 62.448 238.464 62.544 ;
      RECT 0.216 63.216 238.464 63.312 ;
      RECT 0.216 63.984 238.464 64.080 ;
      RECT 0.216 64.752 238.464 64.848 ;
      RECT 0.216 65.520 238.464 65.616 ;
      RECT 0.216 66.288 238.464 66.384 ;
      RECT 0.216 67.056 238.464 67.152 ;
      RECT 0.216 67.824 238.464 67.920 ;
      RECT 0.216 68.592 238.464 68.688 ;
      RECT 0.216 69.360 238.464 69.456 ;
      RECT 0.216 70.128 238.464 70.224 ;
      RECT 0.216 70.896 238.464 70.992 ;
      RECT 0.216 71.664 238.464 71.760 ;
      RECT 0.216 72.432 238.464 72.528 ;
      RECT 0.216 73.200 238.464 73.296 ;
      RECT 0.216 73.968 238.464 74.064 ;
      RECT 0.216 74.736 238.464 74.832 ;
      RECT 0.216 75.504 238.464 75.600 ;
      RECT 0.216 76.272 238.464 76.368 ;
      RECT 0.216 77.040 238.464 77.136 ;
      RECT 0.216 77.808 238.464 77.904 ;
      RECT 0.216 78.576 238.464 78.672 ;
      RECT 0.216 79.344 238.464 79.440 ;
      RECT 0.216 80.112 238.464 80.208 ;
      RECT 0.216 80.880 238.464 80.976 ;
      RECT 0.216 81.648 238.464 81.744 ;
      RECT 0.216 82.416 238.464 82.512 ;
      RECT 0.216 83.184 238.464 83.280 ;
      RECT 0.216 83.952 238.464 84.048 ;
      RECT 0.216 84.720 238.464 84.816 ;
      RECT 0.216 85.488 238.464 85.584 ;
      RECT 0.216 86.256 238.464 86.352 ;
      RECT 0.216 87.024 238.464 87.120 ;
      RECT 0.216 87.792 238.464 87.888 ;
      RECT 0.216 88.560 238.464 88.656 ;
      RECT 0.216 89.328 238.464 89.424 ;
      RECT 0.216 90.096 238.464 90.192 ;
      RECT 0.216 90.864 238.464 90.960 ;
      RECT 0.216 91.632 238.464 91.728 ;
      RECT 0.216 92.400 238.464 92.496 ;
      RECT 0.216 93.168 238.464 93.264 ;
      RECT 0.216 93.936 238.464 94.032 ;
      RECT 0.216 94.704 238.464 94.800 ;
      RECT 0.216 95.472 238.464 95.568 ;
      RECT 0.216 96.240 238.464 96.336 ;
      RECT 0.216 97.008 238.464 97.104 ;
      RECT 0.216 97.776 238.464 97.872 ;
      RECT 0.216 98.544 238.464 98.640 ;
      RECT 0.216 99.312 238.464 99.408 ;
      RECT 0.216 100.080 238.464 100.176 ;
      RECT 0.216 100.848 238.464 100.944 ;
      RECT 0.216 101.616 238.464 101.712 ;
      RECT 0.216 102.384 238.464 102.480 ;
      RECT 0.216 103.152 238.464 103.248 ;
      RECT 0.216 103.920 238.464 104.016 ;
      RECT 0.216 104.688 238.464 104.784 ;
      RECT 0.216 105.456 238.464 105.552 ;
      RECT 0.216 106.224 238.464 106.320 ;
      RECT 0.216 106.992 238.464 107.088 ;
      RECT 0.216 107.760 238.464 107.856 ;
      RECT 0.216 108.528 238.464 108.624 ;
      RECT 0.216 109.296 238.464 109.392 ;
      RECT 0.216 110.064 238.464 110.160 ;
      RECT 0.216 110.832 238.464 110.928 ;
      RECT 0.216 111.600 238.464 111.696 ;
      RECT 0.216 112.368 238.464 112.464 ;
      RECT 0.216 113.136 238.464 113.232 ;
      RECT 0.216 113.904 238.464 114.000 ;
      RECT 0.216 114.672 238.464 114.768 ;
      RECT 0.216 115.440 238.464 115.536 ;
      RECT 0.216 116.208 238.464 116.304 ;
      RECT 0.216 116.976 238.464 117.072 ;
      RECT 0.216 117.744 238.464 117.840 ;
      RECT 0.216 118.512 238.464 118.608 ;
      RECT 0.216 119.280 238.464 119.376 ;
      RECT 0.216 120.048 238.464 120.144 ;
      RECT 0.216 120.816 238.464 120.912 ;
      RECT 0.216 121.584 238.464 121.680 ;
      RECT 0.216 122.352 238.464 122.448 ;
      RECT 0.216 123.120 238.464 123.216 ;
      RECT 0.216 123.888 238.464 123.984 ;
      RECT 0.216 124.656 238.464 124.752 ;
      RECT 0.216 125.424 238.464 125.520 ;
      RECT 0.216 126.192 238.464 126.288 ;
      RECT 0.216 126.960 238.464 127.056 ;
      RECT 0.216 127.728 238.464 127.824 ;
      RECT 0.216 128.496 238.464 128.592 ;
      RECT 0.216 129.264 238.464 129.360 ;
      RECT 0.216 130.032 238.464 130.128 ;
      RECT 0.216 130.800 238.464 130.896 ;
      RECT 0.216 131.568 238.464 131.664 ;
      RECT 0.216 132.336 238.464 132.432 ;
      RECT 0.216 133.104 238.464 133.200 ;
      RECT 0.216 133.872 238.464 133.968 ;
      RECT 0.216 134.640 238.464 134.736 ;
      RECT 0.216 135.408 238.464 135.504 ;
      RECT 0.216 136.176 238.464 136.272 ;
      RECT 0.216 136.944 238.464 137.040 ;
      RECT 0.216 137.712 238.464 137.808 ;
      RECT 0.216 138.480 238.464 138.576 ;
      RECT 0.216 139.248 238.464 139.344 ;
      RECT 0.216 140.016 238.464 140.112 ;
      RECT 0.216 140.784 238.464 140.880 ;
      RECT 0.216 141.552 238.464 141.648 ;
      RECT 0.216 142.320 238.464 142.416 ;
      RECT 0.216 143.088 238.464 143.184 ;
      RECT 0.216 143.856 238.464 143.952 ;
      RECT 0.216 144.624 238.464 144.720 ;
      RECT 0.216 145.392 238.464 145.488 ;
      RECT 0.216 146.160 238.464 146.256 ;
    END
  END VSS
  PIN VDD
    DIRECTION INOUT ;
    USE POWER ;
    PORT
      LAYER M4 ;
      RECT 0.216 0.624 238.464 0.720 ;
      RECT 0.216 1.392 238.464 1.488 ;
      RECT 0.216 2.160 238.464 2.256 ;
      RECT 0.216 2.928 238.464 3.024 ;
      RECT 0.216 3.696 238.464 3.792 ;
      RECT 0.216 4.464 238.464 4.560 ;
      RECT 0.216 5.232 238.464 5.328 ;
      RECT 0.216 6.000 238.464 6.096 ;
      RECT 0.216 6.768 238.464 6.864 ;
      RECT 0.216 7.536 238.464 7.632 ;
      RECT 0.216 8.304 238.464 8.400 ;
      RECT 0.216 9.072 238.464 9.168 ;
      RECT 0.216 9.840 238.464 9.936 ;
      RECT 0.216 10.608 238.464 10.704 ;
      RECT 0.216 11.376 238.464 11.472 ;
      RECT 0.216 12.144 238.464 12.240 ;
      RECT 0.216 12.912 238.464 13.008 ;
      RECT 0.216 13.680 238.464 13.776 ;
      RECT 0.216 14.448 238.464 14.544 ;
      RECT 0.216 15.216 238.464 15.312 ;
      RECT 0.216 15.984 238.464 16.080 ;
      RECT 0.216 16.752 238.464 16.848 ;
      RECT 0.216 17.520 238.464 17.616 ;
      RECT 0.216 18.288 238.464 18.384 ;
      RECT 0.216 19.056 238.464 19.152 ;
      RECT 0.216 19.824 238.464 19.920 ;
      RECT 0.216 20.592 238.464 20.688 ;
      RECT 0.216 21.360 238.464 21.456 ;
      RECT 0.216 22.128 238.464 22.224 ;
      RECT 0.216 22.896 238.464 22.992 ;
      RECT 0.216 23.664 238.464 23.760 ;
      RECT 0.216 24.432 238.464 24.528 ;
      RECT 0.216 25.200 238.464 25.296 ;
      RECT 0.216 25.968 238.464 26.064 ;
      RECT 0.216 26.736 238.464 26.832 ;
      RECT 0.216 27.504 238.464 27.600 ;
      RECT 0.216 28.272 238.464 28.368 ;
      RECT 0.216 29.040 238.464 29.136 ;
      RECT 0.216 29.808 238.464 29.904 ;
      RECT 0.216 30.576 238.464 30.672 ;
      RECT 0.216 31.344 238.464 31.440 ;
      RECT 0.216 32.112 238.464 32.208 ;
      RECT 0.216 32.880 238.464 32.976 ;
      RECT 0.216 33.648 238.464 33.744 ;
      RECT 0.216 34.416 238.464 34.512 ;
      RECT 0.216 35.184 238.464 35.280 ;
      RECT 0.216 35.952 238.464 36.048 ;
      RECT 0.216 36.720 238.464 36.816 ;
      RECT 0.216 37.488 238.464 37.584 ;
      RECT 0.216 38.256 238.464 38.352 ;
      RECT 0.216 39.024 238.464 39.120 ;
      RECT 0.216 39.792 238.464 39.888 ;
      RECT 0.216 40.560 238.464 40.656 ;
      RECT 0.216 41.328 238.464 41.424 ;
      RECT 0.216 42.096 238.464 42.192 ;
      RECT 0.216 42.864 238.464 42.960 ;
      RECT 0.216 43.632 238.464 43.728 ;
      RECT 0.216 44.400 238.464 44.496 ;
      RECT 0.216 45.168 238.464 45.264 ;
      RECT 0.216 45.936 238.464 46.032 ;
      RECT 0.216 46.704 238.464 46.800 ;
      RECT 0.216 47.472 238.464 47.568 ;
      RECT 0.216 48.240 238.464 48.336 ;
      RECT 0.216 49.008 238.464 49.104 ;
      RECT 0.216 49.776 238.464 49.872 ;
      RECT 0.216 50.544 238.464 50.640 ;
      RECT 0.216 51.312 238.464 51.408 ;
      RECT 0.216 52.080 238.464 52.176 ;
      RECT 0.216 52.848 238.464 52.944 ;
      RECT 0.216 53.616 238.464 53.712 ;
      RECT 0.216 54.384 238.464 54.480 ;
      RECT 0.216 55.152 238.464 55.248 ;
      RECT 0.216 55.920 238.464 56.016 ;
      RECT 0.216 56.688 238.464 56.784 ;
      RECT 0.216 57.456 238.464 57.552 ;
      RECT 0.216 58.224 238.464 58.320 ;
      RECT 0.216 58.992 238.464 59.088 ;
      RECT 0.216 59.760 238.464 59.856 ;
      RECT 0.216 60.528 238.464 60.624 ;
      RECT 0.216 61.296 238.464 61.392 ;
      RECT 0.216 62.064 238.464 62.160 ;
      RECT 0.216 62.832 238.464 62.928 ;
      RECT 0.216 63.600 238.464 63.696 ;
      RECT 0.216 64.368 238.464 64.464 ;
      RECT 0.216 65.136 238.464 65.232 ;
      RECT 0.216 65.904 238.464 66.000 ;
      RECT 0.216 66.672 238.464 66.768 ;
      RECT 0.216 67.440 238.464 67.536 ;
      RECT 0.216 68.208 238.464 68.304 ;
      RECT 0.216 68.976 238.464 69.072 ;
      RECT 0.216 69.744 238.464 69.840 ;
      RECT 0.216 70.512 238.464 70.608 ;
      RECT 0.216 71.280 238.464 71.376 ;
      RECT 0.216 72.048 238.464 72.144 ;
      RECT 0.216 72.816 238.464 72.912 ;
      RECT 0.216 73.584 238.464 73.680 ;
      RECT 0.216 74.352 238.464 74.448 ;
      RECT 0.216 75.120 238.464 75.216 ;
      RECT 0.216 75.888 238.464 75.984 ;
      RECT 0.216 76.656 238.464 76.752 ;
      RECT 0.216 77.424 238.464 77.520 ;
      RECT 0.216 78.192 238.464 78.288 ;
      RECT 0.216 78.960 238.464 79.056 ;
      RECT 0.216 79.728 238.464 79.824 ;
      RECT 0.216 80.496 238.464 80.592 ;
      RECT 0.216 81.264 238.464 81.360 ;
      RECT 0.216 82.032 238.464 82.128 ;
      RECT 0.216 82.800 238.464 82.896 ;
      RECT 0.216 83.568 238.464 83.664 ;
      RECT 0.216 84.336 238.464 84.432 ;
      RECT 0.216 85.104 238.464 85.200 ;
      RECT 0.216 85.872 238.464 85.968 ;
      RECT 0.216 86.640 238.464 86.736 ;
      RECT 0.216 87.408 238.464 87.504 ;
      RECT 0.216 88.176 238.464 88.272 ;
      RECT 0.216 88.944 238.464 89.040 ;
      RECT 0.216 89.712 238.464 89.808 ;
      RECT 0.216 90.480 238.464 90.576 ;
      RECT 0.216 91.248 238.464 91.344 ;
      RECT 0.216 92.016 238.464 92.112 ;
      RECT 0.216 92.784 238.464 92.880 ;
      RECT 0.216 93.552 238.464 93.648 ;
      RECT 0.216 94.320 238.464 94.416 ;
      RECT 0.216 95.088 238.464 95.184 ;
      RECT 0.216 95.856 238.464 95.952 ;
      RECT 0.216 96.624 238.464 96.720 ;
      RECT 0.216 97.392 238.464 97.488 ;
      RECT 0.216 98.160 238.464 98.256 ;
      RECT 0.216 98.928 238.464 99.024 ;
      RECT 0.216 99.696 238.464 99.792 ;
      RECT 0.216 100.464 238.464 100.560 ;
      RECT 0.216 101.232 238.464 101.328 ;
      RECT 0.216 102.000 238.464 102.096 ;
      RECT 0.216 102.768 238.464 102.864 ;
      RECT 0.216 103.536 238.464 103.632 ;
      RECT 0.216 104.304 238.464 104.400 ;
      RECT 0.216 105.072 238.464 105.168 ;
      RECT 0.216 105.840 238.464 105.936 ;
      RECT 0.216 106.608 238.464 106.704 ;
      RECT 0.216 107.376 238.464 107.472 ;
      RECT 0.216 108.144 238.464 108.240 ;
      RECT 0.216 108.912 238.464 109.008 ;
      RECT 0.216 109.680 238.464 109.776 ;
      RECT 0.216 110.448 238.464 110.544 ;
      RECT 0.216 111.216 238.464 111.312 ;
      RECT 0.216 111.984 238.464 112.080 ;
      RECT 0.216 112.752 238.464 112.848 ;
      RECT 0.216 113.520 238.464 113.616 ;
      RECT 0.216 114.288 238.464 114.384 ;
      RECT 0.216 115.056 238.464 115.152 ;
      RECT 0.216 115.824 238.464 115.920 ;
      RECT 0.216 116.592 238.464 116.688 ;
      RECT 0.216 117.360 238.464 117.456 ;
      RECT 0.216 118.128 238.464 118.224 ;
      RECT 0.216 118.896 238.464 118.992 ;
      RECT 0.216 119.664 238.464 119.760 ;
      RECT 0.216 120.432 238.464 120.528 ;
      RECT 0.216 121.200 238.464 121.296 ;
      RECT 0.216 121.968 238.464 122.064 ;
      RECT 0.216 122.736 238.464 122.832 ;
      RECT 0.216 123.504 238.464 123.600 ;
      RECT 0.216 124.272 238.464 124.368 ;
      RECT 0.216 125.040 238.464 125.136 ;
      RECT 0.216 125.808 238.464 125.904 ;
      RECT 0.216 126.576 238.464 126.672 ;
      RECT 0.216 127.344 238.464 127.440 ;
      RECT 0.216 128.112 238.464 128.208 ;
      RECT 0.216 128.880 238.464 128.976 ;
      RECT 0.216 129.648 238.464 129.744 ;
      RECT 0.216 130.416 238.464 130.512 ;
      RECT 0.216 131.184 238.464 131.280 ;
      RECT 0.216 131.952 238.464 132.048 ;
      RECT 0.216 132.720 238.464 132.816 ;
      RECT 0.216 133.488 238.464 133.584 ;
      RECT 0.216 134.256 238.464 134.352 ;
      RECT 0.216 135.024 238.464 135.120 ;
      RECT 0.216 135.792 238.464 135.888 ;
      RECT 0.216 136.560 238.464 136.656 ;
      RECT 0.216 137.328 238.464 137.424 ;
      RECT 0.216 138.096 238.464 138.192 ;
      RECT 0.216 138.864 238.464 138.960 ;
      RECT 0.216 139.632 238.464 139.728 ;
      RECT 0.216 140.400 238.464 140.496 ;
      RECT 0.216 141.168 238.464 141.264 ;
      RECT 0.216 141.936 238.464 142.032 ;
      RECT 0.216 142.704 238.464 142.800 ;
      RECT 0.216 143.472 238.464 143.568 ;
      RECT 0.216 144.240 238.464 144.336 ;
      RECT 0.216 145.008 238.464 145.104 ;
      RECT 0.216 145.776 238.464 145.872 ;
      RECT 0.216 146.544 238.464 146.640 ;
    END
  END VDD
  OBS
    LAYER M1 ;
    RECT 0 0 238.680 146.881 ;
    LAYER M2 ;
    RECT 0 0 238.680 146.881 ;
    LAYER M3 ;
    RECT 0 0 238.680 146.881 ;
    LAYER M4 ;
    RECT 0 0 238.680 146.881 ;
  END
END fakeram_1rw1r_130w512d_sram

END LIBRARY
